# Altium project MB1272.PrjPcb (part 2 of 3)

## Sheet Peripherals.SchDoc: Peripherals
size A4; Date: 01-DEC-2013; CompanyName: STMicroelectronics; Organization: Microcontrollers Division; Address1: 12, Rue Jules HOROWITZ; Address2: 38019 Grenoble; Address3: FRANCE; DocumentNumber: MB1272; Revision: A-01; SheetNumber: 13; SheetTotal: 15; Project: STM32MP15-DISCO PI

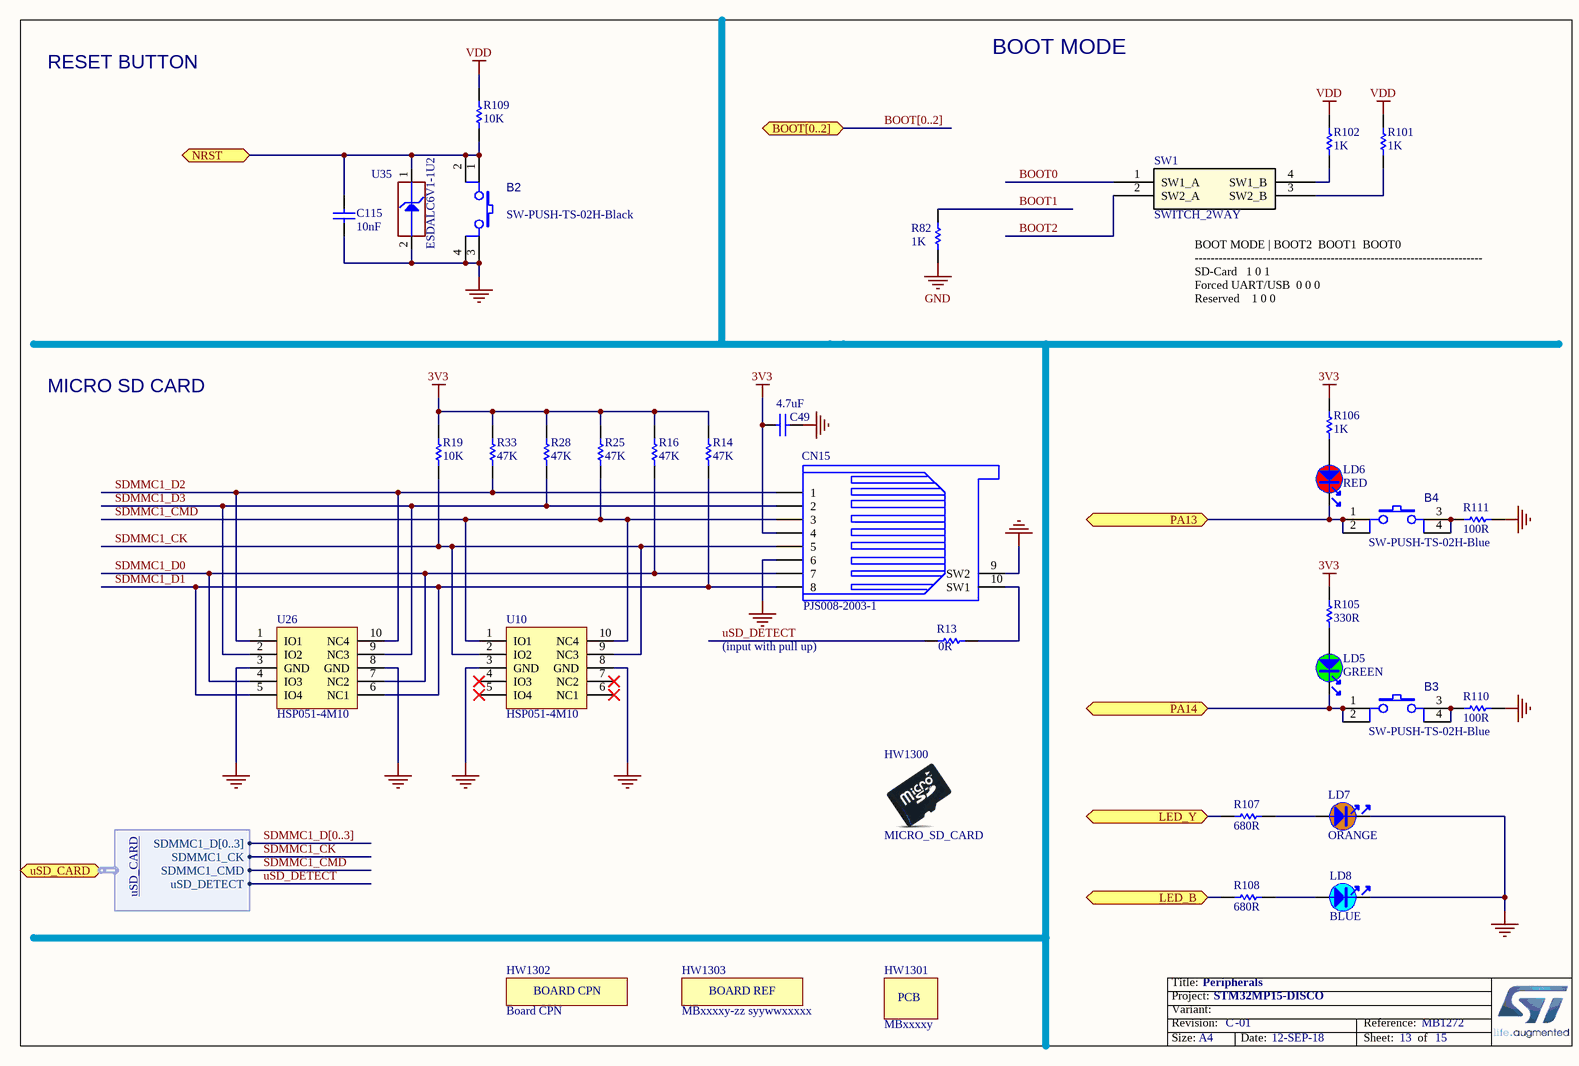
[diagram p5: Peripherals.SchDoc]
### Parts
B2  value SW-PUSH-TS-02H-Black  [SWI_JIUBABA_C-TS-02H-2-5-K-V-T_R_BLACK]
B3  SW-PUSH-TS-02H-Blue  [SWI_JIUBABA_C-TS-02H-2-5-B-V-T_R_BLUE]
B4  SW-PUSH-TS-02H-Blue  [SWI_JIUBABA_C-TS-02H-2-5-B-V-T_R_BLUE]
C49  value 4.7uF  [C0402]  (hidden comment: Capacitor)
C115  value 10nF  [C0402]  (hidden comment: Capacitor)
CN15  value PJS008-2003-1  [CON_MICROSD_YAMAICHI_PJS008-2003-0]
HW1300  Micro_SD_card  (mechanical)
HW1301  value MBxxxxy  (hidden comment: PCB)  (mechanical)
HW1302  value Board CPN  [STICKER_BOARD-CPN_25X5]  (hidden comment: ​PCH W35 footprint requested to have a space on board for stickers.)  (mechanical)
HW1303  value MBxxxxy-zz syywwxxxxx  [STICKER_BOARD-REF_25X5]  (hidden comment: STICKER_BOARD_REF)  (mechanical)
LD5  value GREEN  [LED_0603_GREEN]
LD6  value RED  [LED_0603_RED]
LD7  value ORANGE  [LED_0603_ORANGE_H0P4]  (hidden comment: LED_orange)
LD8  value BLUE  [LED_0603_SMD-B_BLUE_H0P4]  (hidden comment: ​reference from jiubaba)
R13  value 0R  [R0402]
R14  value 47K  [R0402]
R16  value 47K  [R0402]
R19  value 10K  [R0402]
R25  value 47K  [R0402]
R28  value 47K  [R0402]
R33  value 47K  [R0402]
R82  value 1K  [R0402]  (hidden comment: Resistor)
R101  value 1K  [R0402]
R102  value 1K  [R0402]
R105  value 330R  [R0402]
R106  value 1K  [R0402]
R107  value 680R  [R0402]  (hidden comment: Resistor)
R108  value 680R  [R0402]  (hidden comment: Resistor)
R109  value 10K  [R0402]
R110  value 100R  [R0402]
R111  value 100R  [R0402]
SW1  SWITCH_2WAY  [SWI_C&K_SDA02H1SBD_2POS]
U10  HSP051-4M10  [ESD_UQFN-10L_2P5X1_P050]
U26  HSP051-4M10  [ESD_UQFN-10L_2P5X1_P050]
U35  value ESDALC6V1-1U2  [ESD_ST0201]  (hidden comment: ESD-TRANSIL)

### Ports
BOOT[0..2], LED_B, LED_Y, NRST (bidir), PA13, PA14, uSD_CARD (harness uSD_CARD)

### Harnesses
uSD_CARD: SDMMC1_D[0..3], SDMMC1_CK, SDMMC1_CMD, uSD_DETECT

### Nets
3V3: C49.2 CN15.4 R14.2 R16.2 R19.2 R25.2 R28.2 R33.2 R105.2 R106.2
GND: B2.3 B2.4 C49.1 C115.1 CN15.6 CN15.9(SW2) LD7.2 LD8.2 R82.1 R110.2 R111.2 U10.3(GND) U10.8(GND) U26.3(GND) U26.8(GND) U35.2(GND)
VDD: R101.2 R102.2 R109.2
BOOT0: SW1.1(SW1_A)
BOOT1: R82.2
BOOT2: SW1.2(SW2_A)
LED_B: R108.1 ; port LED_B
LED_Y: R107.1 ; port LED_Y
NRST: B2.1 B2.2 C115.2 R109.1 U35.1(IO1) ; port NRST
PA13: B4.1 B4.2 LD6.2 ; port PA13
PA14: B3.1 B3.2 LD5.2 ; port PA14
SDMMC1_CK: CN15.5 R19.1 U10.2(IO2) U10.9(NC3) ; port uSD_CARD.SDMMC1_CK
SDMMC1_CMD: CN15.3 R25.1 U10.1(IO1) U10.10(NC4) ; port uSD_CARD.SDMMC1_CMD
SDMMC1_D0: CN15.7 R16.1 U26.4(IO3) U26.7(NC2)
SDMMC1_D1: CN15.8 R14.1 U26.5(IO4) U26.6(NC1)
SDMMC1_D2: CN15.1 R33.1 U26.1(IO1) U26.10(NC4)
SDMMC1_D3: CN15.2 R28.1 U26.2(IO2) U26.9(NC3)
uSD_DETECT: R13.1 ; port uSD_CARD.uSD_DETECT
NetB3_3: B3.3 B3.4 R110.1
NetB4_3: B4.3 B4.4 R111.1
NetCN15_10: CN15.10(SW1) R13.2
NetLD5_1: LD5.1 R105.1
NetLD6_1: LD6.1 R106.1
NetLD7_1: LD7.1 R107.2
NetLD8_1: LD8.1 R108.2
NetR101_1: R101.1 SW1.3(SW2_B)
NetR102_1: R102.1 SW1.4(SW1_B)

Not connected (* = marked no-connect by the designer): U10 4(IO3)* 5(IO4)* 6(NC1)* 7(NC2)*

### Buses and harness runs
bus BOOT[0..2] = port BOOT[0..2]
bus SDMMC1_D[0..3]

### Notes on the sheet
- BOOT MODE
- RESET BUTTON
- (near SW1) BOOT MODE	|	BOOT2 	BOOT1 	BOOT0
  ------------------------------------------------------------------------
  SD-Card			1	0	1
  Forced UART/USB		0	0	0
  Reserved 			1	0	0
- MICRO SD CARD
- (input with pull up)

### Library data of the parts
B2 = MCD-00171: Switch HW SMD black; Manufacturer_Part_Number: C-TS-02H-2.5-K-V-T/R BLACK; Manufacturer: JIUBABA; Part_Type: Misc; Provided_By: SUBCO; Initial_Board_Reference: MB1264
B3 B4 = MCD-00172: Switch HW SMD blue; Part_Type: Misc; Manufacturer_Part_Number: C-TS-02H-2.5-B-V-T/R BLUE; Manufacturer: JIUBABA; Provided_By: SUBCO; Initial_Board_Reference: MB1264
C49 = MCD-01356: Capacitor, MLCC, 4.7uF, 6V3, X5R, 20%, 0402, T=0,5mm; Manufacturer_Part_Number: GRM155R60J475ME47; Manufacturer: MURATA; Provided_By: SUBCO
C115 = MCD-00011: Capacitor, MLCC, 10nF, 16V, X7R, 10%, 0402, T=0.5mm; Manufacturer_Part_Number: CC0402KRX7R7BB103; Manufacturer: YAGEO; Provided_By: SUBCO; Initial_Board_Reference: MB1274
CN15 = MCD-00023: MicroSD Card Conn, Reversed-Type, Mnt Push-Push; Manufacturer: YAMAICHI; Part_Type: Connector; Provided_By: SUBCO; Initial_Board_Reference: mb1274
HW1300 = MCD-01200: MICRO_SD_CARD Standard min 4GB; Part_Type: Misc; Manufacturer: NETAC; Alternate_Manufacturer: Jiubaba; Alternate_Manufacturer_Part_Number: 988.05.20.3.00018; Provided_By: SUBCO; Initial_Board_Reference: MB1372
HW1301 = MCD-00216: PCB, xxxx for PCB ref, Y for revision; Part_Type: Mechanical; Provided_By: SUBCO; Initial_Board_Reference: MB1319
HW1302 = MCD-00547: Sticker to mention board CPN code; Part_Type: Mechanical; Provided_By: SUBCO; Initial_Board_Reference: MB1319
HW1303 = MCD-00235: Sticker to mention board reference + serial number; Part_Type: Mechanical; Provided_By: SUBCO; Initial_Board_Reference: MB1319
LD5 = MCD-00050: LED, Green, 0603; Manufacturer_Part_Number: 19-213SYGC/S530-E2/TR8; Manufacturer: EVERLIGHT; Part_Type: Display; ECCN_US: EAR99; ECCN_EU: NEC; Provided_By: SUBCO; Initial_Board_Reference: mb1274
LD6 = MCD-00049: LED, Red, 0603; Manufacturer_Part_Number: 19-213-R6C-AP1Q2B/3T; Manufacturer: EVERLIGHT; Part_Type: Display; ECCN_US: EAR99; ECCN_EU: NEC; Provided_By: SUBCO; Initial_Board_Reference: mb1274
LD7 = MCD-00321: LED, Orange, 0603; Part_Type: Display; Manufacturer_Part_Number: 19-217/S2C-AM2N2VY/3T; Manufacturer: EVERLIGHT; ECCN_US: EAR99; ECCN_EU: NEC; Provided_By: SUBCO; Initial_Board_Reference: MB1311
LD8 = MCD-01131: LED Blue, 0603 SMD, Forward Voltage Min=2,8V, Max=3,1V; Part_Type: Display; Manufacturer_Part_Number: 19-217-BHC-ZL1M2RY-3T; Manufacturer: EVERLIGHT; Provided_By: SUBCO; Initial_Board_Reference: MB1272
R13 = MCD-00052: Resistor,0R,0402,5%,1/16W; Manufacturer_Part_Number: RC0402JR-070RL; Manufacturer: YAGEO; Provided_By: SUBCO; Initial_Board_Reference: mb1274
R14 R16 R25 R28 R33 = MCD-00063: Resistor,47K,0402,1%,1/16W; Manufacturer_Part_Number: RC0402FR-0747KL; Manufacturer: YAGEO; Provided_By: SUBCO; Initial_Board_Reference: mb1274
R19 R109 = MCD-00053: Resistor,10K,0402,1%,1/16W; Manufacturer_Part_Number: RC0402FR-0710KL; Manufacturer: YAGEO; Provided_By: SUBCO; Initial_Board_Reference: mb1274
R82 = MCD-00061: Resistor,1K,0402,1%,1/16W; Manufacturer_Part_Number: RC0402FR-071KL; Manufacturer: YAGEO; Provided_By: SUBCO; Initial_Board_Reference: MB1274
R101 R102 R106 = MCD-00061: Resistor,1K,0402,1%,1/16W; Manufacturer_Part_Number: RC0402FR-071KL; Manufacturer: YAGEO; Provided_By: SUBCO; Initial_Board_Reference: mb1274
R105 = MCD-00062: Resistor,330R,0402,1%,1/16W; Manufacturer_Part_Number: RC0402FR-07330RL; Manufacturer: YAGEO; Provided_By: SUBCO; Initial_Board_Reference: mb1274
R107 R108 = MCD-00507: Resistor,680R,0402,1%,1/16W; Manufacturer_Part_Number: RC0402FR-07680RL; Manufacturer: YAGEO; Provided_By: SUBCO
R110 R111 = MCD-00067: Resistor,100R,0402,1%,1/16W; Manufacturer_Part_Number: RC0402FR-07100RL; Manufacturer: YAGEO; Provided_By: SUBCO; Initial_Board_Reference: mb1274
SW1 = MCD-00658: Dip Switch ,2Position ,Surface Mount Slide (Standard) ,2.54 pitch,25mA 24VDC; Part_Type: Misc; Manufacturer_Part_Number: SDA02H1SBD; Manufacturer: C&K; Provided_By: SUBCO; Initial_Board_Reference: MB1272
U10 U26 = MCD-00667: 4-line ESD protection for high speed lines; Part_Type: Diode; Manufacturer: STMICROELECTRONICS; BMS_Part_Number: 9179041; ECCN_US: EAR99; ECCN_EU: NEC; Provided_By: SUBCO with ST control; Initial_Board_Reference: MB1331
U35 = MCD-00170: ESD protection 6V1; Part_Type: Diode; Manufacturer: STMICROELECTRONICS; BMS_Part_Number: 9151132; ECCN_US: EAR99; ECCN_EU: NEC; Provided_By: SUBCO with ST control; Initial_Board_Reference: MB1274

## Sheet ST_LINK_V2-1.SCHDOC: ST-LINK/V2-1 with support of SWD only
size A4; Author: A.B; CompanyName: STMicroelectronics; Organization: Microcontrollers Division; Address1: 12, Rue Jules HOROWITZ; Address2: 38019 Grenoble; Address3: FRANCE; DocumentNumber: MB1272; Revision: A-01; SheetNumber: 15; SheetTotal: 15; Project: STM32MP15-DISCO PI

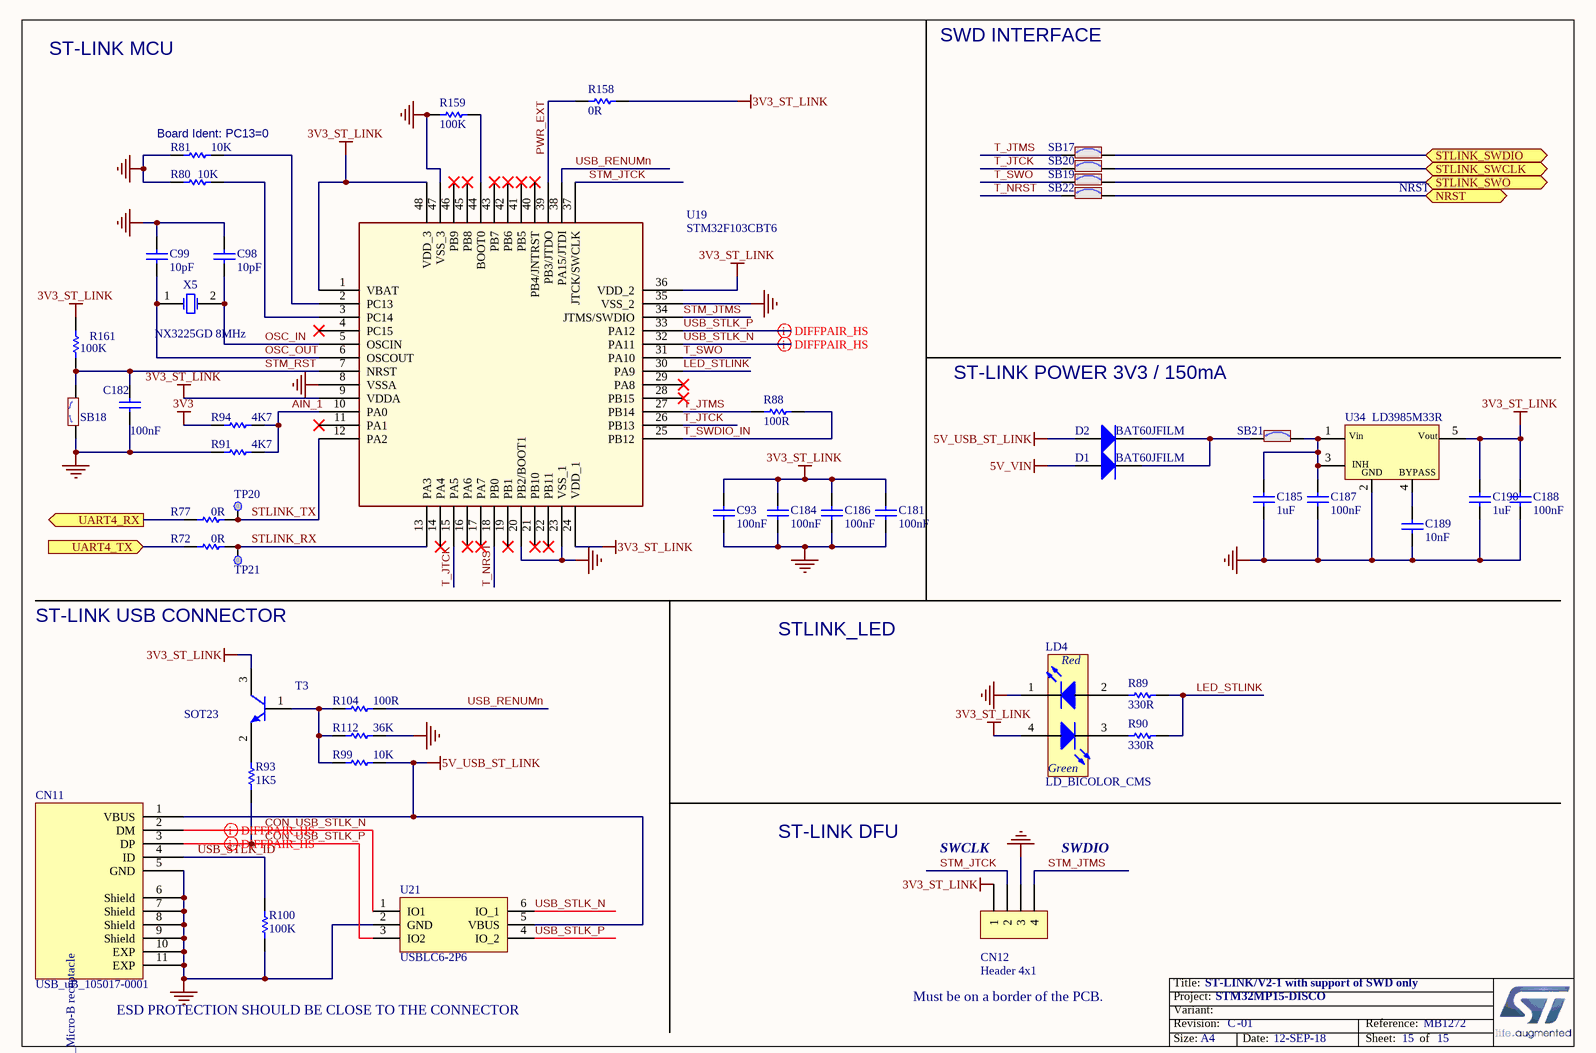
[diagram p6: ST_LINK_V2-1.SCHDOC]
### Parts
C93  value 100nF  [C0402]
C98  value 10pF  [C0402]
C99  value 10pF  [C0402]
C181  value 100nF  [C0402]
C182  value 100nF  [C0402]
C184  value 100nF  [C0402]
C185  value 1uF  [C0603]
C186  value 100nF  [C0402]
C187  value 100nF  [C0402]
C188  value 100nF  [C0402]
C189  value 10nF  [C0402]
C190  value 1uF  [C0603]
CN11  value USB_uB_105017-0001  [CON_USBMICROB_MOLEX_105017-0001_H2P90]
CN12  value Header 4x1  [CON_SAMTEC_TSW-104-07-G-S]
D1  value BAT60JFILM  [DIO_SOD323]
D2  value BAT60JFILM  [DIO_SOD323]
LD4  value LD_BICOLOR_CMS  [LED_BI-GR_HSMF-A201-A00J1]
R72  value 0R  [R0402]
R77  value 0R  [R0402]
R80  value 10K  [R0402]
R81  value 10K  [R0402]
R88  value 100R  [R0402]
R89  value 330R  [R0402]
R90  value 330R  [R0402]
R91  value 4K7  [R0402]
R93  value 1K5  [R0402]
R94  value 4K7  [R0402]
R99  value 10K  [R0402]
R100  value 100K  [R0402]
R104  value 100R  [R0402]
R112  value 36K  [R0402]
R158  value 0R  [R0402]
R159  value 100K  [R0402]
R161  value 100K  [R0402]
SB17  (no value)  [SOLDER-BRIDGE_R0603-0R]
SB18  (no value)  [SOLDER-BRIDGE_R0603-0R]
SB19  (no value)  [SOLDER-BRIDGE_R0603-0R]
SB20  (no value)  [SOLDER-BRIDGE_R0603-0R]
SB21  (no value)  [SOLDER-BRIDGE_R0603-0R]
SB22  (no value)  [SOLDER-BRIDGE_R0603-0R]
T3  value SOT23  [NPN_SOT23]
TP20  Test Point  [TP_SMD_1MM]  (value not drawn)  (no BOM)
TP21  Test Point  [TP_SMD_1MM]  (value not drawn)  (no BOM)
U19  value STM32F103CBT6  [ICC_LQFP48_7X7_P050]
U21  value USBLC6-2P6  [ESD_SOT666]
U34  value LD3985M33R  [REG_SOT23-5L]
X5  value NX3225GD 8MHz  [CRY_NX3225GD_2P]

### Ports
NRST (bidir), STLINK_SWCLK, STLINK_SWDIO, STLINK_SWO, UART4_RX (out), UART4_TX (in)

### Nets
3V3: R94.1
3V3_ST_LINK: C93.2 C181.2 C184.2 C186.2 C188.2 C190.2 CN12.1 LD4.4(YellowGreen_anode) R158.2 R161.2 T3.3(C) U19.1(VBAT) U19.9(VDDA) U19.24(VDD_1) U19.36(VDD_2) U19.48(VDD_3) U34.5(Vout)
5V_USB_ST_LINK: CN11.1(VBUS) D2.1(A) R99.1 U21.5(VBUS)
5V_VIN: D1.1(A)
GND: C93.1 C98.2 C99.2 C181.1 C182.1 C184.1 C185.2 C186.1 C187.1 C188.1 C189.1 C190.1 CN11.5(GND) CN11.6(Shield) CN11.7(Shield) CN11.8(Shield) CN11.9(Shield) CN11.10(EXP) CN11.11(EXP) CN12.3 LD4.1(RED_cathode) R80.1 R81.2 R91.1 R100.1 R112.1 R159.1 SB18.1 U19.8(VSSA) U19.20(PB2/BOOT1) U19.23(VSS_1) U19.35(VSS_2) U19.47(VSS_3) U21.2(GND) U34.2(GND)
AIN_1: R91.2 R94.2 U19.10(PA0)
CON_USB_STLK_N: CN11.2(DM) U21.1(IO1)
CON_USB_STLK_P: CN11.3(DP) R93.1 U21.3(IO2)
JTDO_TRACESWO: SB19.2 ; port STLINK_SWO
LED_STLINK: R89.2 R90.2 U19.30(PA9)
NRST: SB22.2 ; port NRST
OSC_IN: C98.1 U19.5(OSCIN) X5.2(OSC2)
OSC_OUT: C99.1 U19.6(OSCOUT) X5.1(OSC1)
PWR_EXT: R158.1 U19.39(PB3/JTDO)
STLINK_RX: R72.2 TP21.1 U19.13(PA3)
STLINK_SWCLK: SB20.2 ; port STLINK_SWCLK
STLINK_SWDIO: SB17.2 ; port STLINK_SWDIO
STLINK_TX: R77.1 TP20.1 U19.12(PA2)
STM_JTCK: CN12.2 U19.37(JTCK/SWCLK)
STM_JTMS: CN12.4 U19.34(JTMS/SWDIO)
STM_RST: C182.2 R161.1 SB18.2 U19.7(NRST)
T_JTCK: SB20.1 U19.15(PA5) U19.26(PB13)
T_JTMS: R88.1 SB17.1 U19.27(PB14)
T_NRST: SB22.1 U19.18(PB0)
T_SWDIO_IN: R88.2 U19.25(PB12)
T_SWO: SB19.1 U19.31(PA10)
UART4_RX: R77.2 ; port UART4_RX
UART4_TX: R72.1 ; port UART4_TX
USB_RENUMn: R104.2 U19.38(PA15/JTDI)
USB_STLK_ID: CN11.4(ID) R100.2
USB_STLK_N: U19.32(PA11) U21.6(IO_1)
USB_STLK_P: U19.33(PA12) U21.4(IO_2)
NetC185_1: C185.1 C187.2 SB21.2 U34.1(Vin) U34.3(CE)
NetC189_2: C189.2 U34.4(BYPASS)
NetD1_2: D1.2(K) D2.2(K) SB21.1
NetLD4_2: LD4.2(Red_anode) R89.1
NetLD4_3: LD4.3(YellowGreen_cathode) R90.1
NetR80_2: R80.2 U19.3(PC14)
NetR81_1: R81.1 U19.2(PC13)
NetR93_2: R93.2 T3.2(E)
NetR99_2: R99.2 R104.1 R112.2 T3.1(B)
NetR159_2: R159.2 U19.44(BOOT0)

Not connected (* = marked no-connect by the designer): U19 4(PC15)* 11(PA1)* 14(PA4)* 16(PA6)* 17(PA7)* 19(PB1)* 21(PB10)* 22(PB11)* 28(PB15)* 29(PA8)* 40(PB4/JNTRST)* 41(PB5)* 42(PB6)* 43(PB7)* 45(PB8)* 46(PB9)*

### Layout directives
differential pair: CON_USB_STLK_N, CON_USB_STLK_P, USB_STLK_N, USB_STLK_P

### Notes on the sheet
- ST-LINK MCU
- SWD INTERFACE
- (near R81) Board Ident: PC13=0
- NRST
- ST-LINK POWER 3V3 / 150mA
- ST-LINK USB CONNECTOR
- STLINK_LED
- ST-LINK DFU
- SWCLK
- SWDIO
- Must be on a border of the PCB.
- (near CN11) ESD PROTECTION SHOULD BE CLOSE TO THE CONNECTOR

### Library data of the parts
C93 C181 C182 C184 C186-C188 = MCD-00006: Capacitor,100nF,16V,X7R,10%,0402; Manufacturer_Part_Number: CC0402KRX7R7BB104; Manufacturer: YAGEO; Alternate_Manufacturer: MURATA; Alternate_Manufacturer_Part_Number: GCM155R71C104KA55D; Provided_By: SUBCO; Initial_Board_Reference: mb1274
C98 C99 = MCD-00015: Capacitor,10pF,50V,NPO,5%,0402; Manufacturer_Part_Number: CC0402JRNPO9BN100; Manufacturer: YAGEO; Provided_By: SUBCO; Initial_Board_Reference: mb1274
C185 C190 = MCD-00238: Capacitor,1uF,6V3,X5R,10%,0603; Manufacturer_Part_Number: CC0603KRX5R5BB105; Manufacturer: YAGEO; Provided_By: SUBCO; Initial_Board_Reference: mb1319
C189 = MCD-00011: Capacitor,10nF,16V,X7R,10%,0402; Manufacturer_Part_Number: CC0402KRX7R7BB103; Manufacturer: YAGEO; Provided_By: SUBCO; Initial_Board_Reference: mb1274
CN11 = MCD-00028: USB-MICRO-B, 0.65mm, RA, SMT, Bottom Mount,; Manufacturer_Part_Number: 1050170001; Manufacturer: MOLEX; Part_Type: Connector; Provided_By: SUBCO; Initial_Board_Reference: mb1274
CN12 = MCD-00029: Header, 4x1, 2,54mm, VR, TH, Height 5.84mm/2.54mm; Manufacturer_Part_Number: TSW-104-07-x-S; Manufacturer: SAMTEC; Part_Type: Connector; Provided_By: SUBCO; Initial_Board_Reference: mb1274
D1 D2 = MCD-00034: BAT60JFILM; Manufacturer: STMICROELECTRONICS; Part_Type: Diode; BMS_Part_Number: 9151097; ECCN_US: EAR99; ECCN_EU: NEC; Provided_By: SUBCO with ST control; Initial_Board_Reference: mb1274
LD4 = MCD-00051: LED Bicolor; Manufacturer_Part_Number: HSMF-A201-A00J1; Manufacturer: AVAGO TECHNOLOGIES; Alternate_Manufacturer_Part_Number: LE-RGW35280; Alternate_Manufacturer: EVERLUCK; Part_Type: Display; ECCN_US: EAR99; ECCN_EU: NEC; Provided_By: SUBCO; Initial_Board_Reference: mb1274
R72 R77 R158 = MCD-00052: as R13 on sheet Peripherals
R80 R81 R99 = MCD-00053: as R19 on sheet Peripherals
R88 R104 = MCD-00067: as R110 on sheet Peripherals
R89 R90 = MCD-00062: as R105 on sheet Peripherals
R91 R94 = MCD-00065: Resistor,4K7,0402,1%,1/16W; Manufacturer_Part_Number: RC0402FR-074K7L; Manufacturer: YAGEO; Alternate_Manufacturer_Part_Number: RT0402FRE074K7L; Provided_By: SUBCO; Initial_Board_Reference: mb1274
R93 = MCD-00068: Resistor,1K5,0402,1%,1/16W; Manufacturer_Part_Number: RC0402FR-071K5L; Manufacturer: YAGEO; Provided_By: SUBCO; Initial_Board_Reference: mb1274
R100 R159 R161 = MCD-00059: Resistor,100K,0402,1%,1/16W; Manufacturer_Part_Number: RC0402FR-07100KL; Manufacturer: YAGEO; Alternate_Manufacturer_Part_Number: RT0402FRE07100KL; Provided_By: SUBCO; Initial_Board_Reference: mb1274
R112 = MCD-00069: Resistor,36K,0402,1%,1/16W; Manufacturer_Part_Number: RC0402FR-0736KL; Manufacturer: YAGEO; Provided_By: SUBCO; Initial_Board_Reference: mb1274
SB17 SB19-SB22 = MCD-00071: Solder Bridge ON; Part_Type: Mechanical; Manufacturer: YAGEO; Manufacturer_Part_Number: RC0603JR-070RL; Provided_By: SUBCO; Initial_Board_Reference: mb1274
SB18 = MCD-00072: Solder Bridge OFF; Part_Type: Mechanical; Manufacturer: YAGEO; Manufacturer_Part_Number: RC0603JR-070RL; Provided_By: SUBCO; Initial_Board_Reference: mb1274
T3 = MCD-00073: NPN Bipolar Transistor; Manufacturer_Part_Number: BSR14; Manufacturer: ON SEMICONDUCTOR; Part_Type: IC; Alternate_Manufacturer_Part_Number: MMBT2222ALT1G / MMBT2222ALT3G; ECCN_US: EAR99; ECCN_EU: NEC; Provided_By: SUBCO; Initial_Board_Reference: mb1274
TP20 TP21 = MCD-00074: Test Point 1mm; Part_Type: Mechanical; Initial_Board_Reference: MB1274
U19 = MCD-00085: Medium-density performance line ARM-based 32-bit MCU with 128KB Flash; Manufacturer: STMICROELECTRONICS; Part_Type: IC; BMS_Part_Number: 9175111; ECCN_US: 3A991A2; ECCN_EU: NEC; Provided_By: SUBCO with ST control; Initial_Board_Reference: mb1274
U21 = MCD-00169: USB OTG FS ESD protection; Manufacturer: STMICROELECTRONICS; Part_Type: IC; BMS_Part_Number: 9151057; Provided_By: SUBCO with ST control; ECCN_US: EAR99; ECCN_EU: NEC; Initial_Board_Reference: MB1274
U34 = MCD-00086: Ultra low drop-low noise BiCMOS voltage, regulators low ESR capacitors compatible; Manufacturer: STMICROELECTRONICS; Part_Type: IC; BMS_Part_Number: 9176161; ECCN_US: EAR99; ECCN_EU: NEC; Provided_By: SUBCO with ST control; Initial_Board_Reference: mb1274
X5 = MCD-00092: Crystal 8Mhz, 8pF, -+50PPM, SMD; Manufacturer_Part_Number: NX3225GD 8MHz EXS00A-CG04874; Manufacturer: NDK; Part_Type: Crystal_Osc; BMS_Part_Number: 9157029; ECCN_US: EAR99; ECCN_EU: NEC; Provided_By: SUBCO; Initial_Board_Reference: mb1274

## Sheet GPIO_&_Arduino_ Connectors.SchDoc: GPIO_&_Arduino_ Connectors
size A3; CompanyName: STMicroelectronics; Organization: Microcontrollers Division; Address1: 12, Rue Jules HOROWITZ; Address2: 38019 Grenoble; Address3: FRANCE; DocumentNumber: MB1272; Revision: A-01; SheetNumber: 10; SheetTotal: 15; Project: STM32MP15-DISCO PI

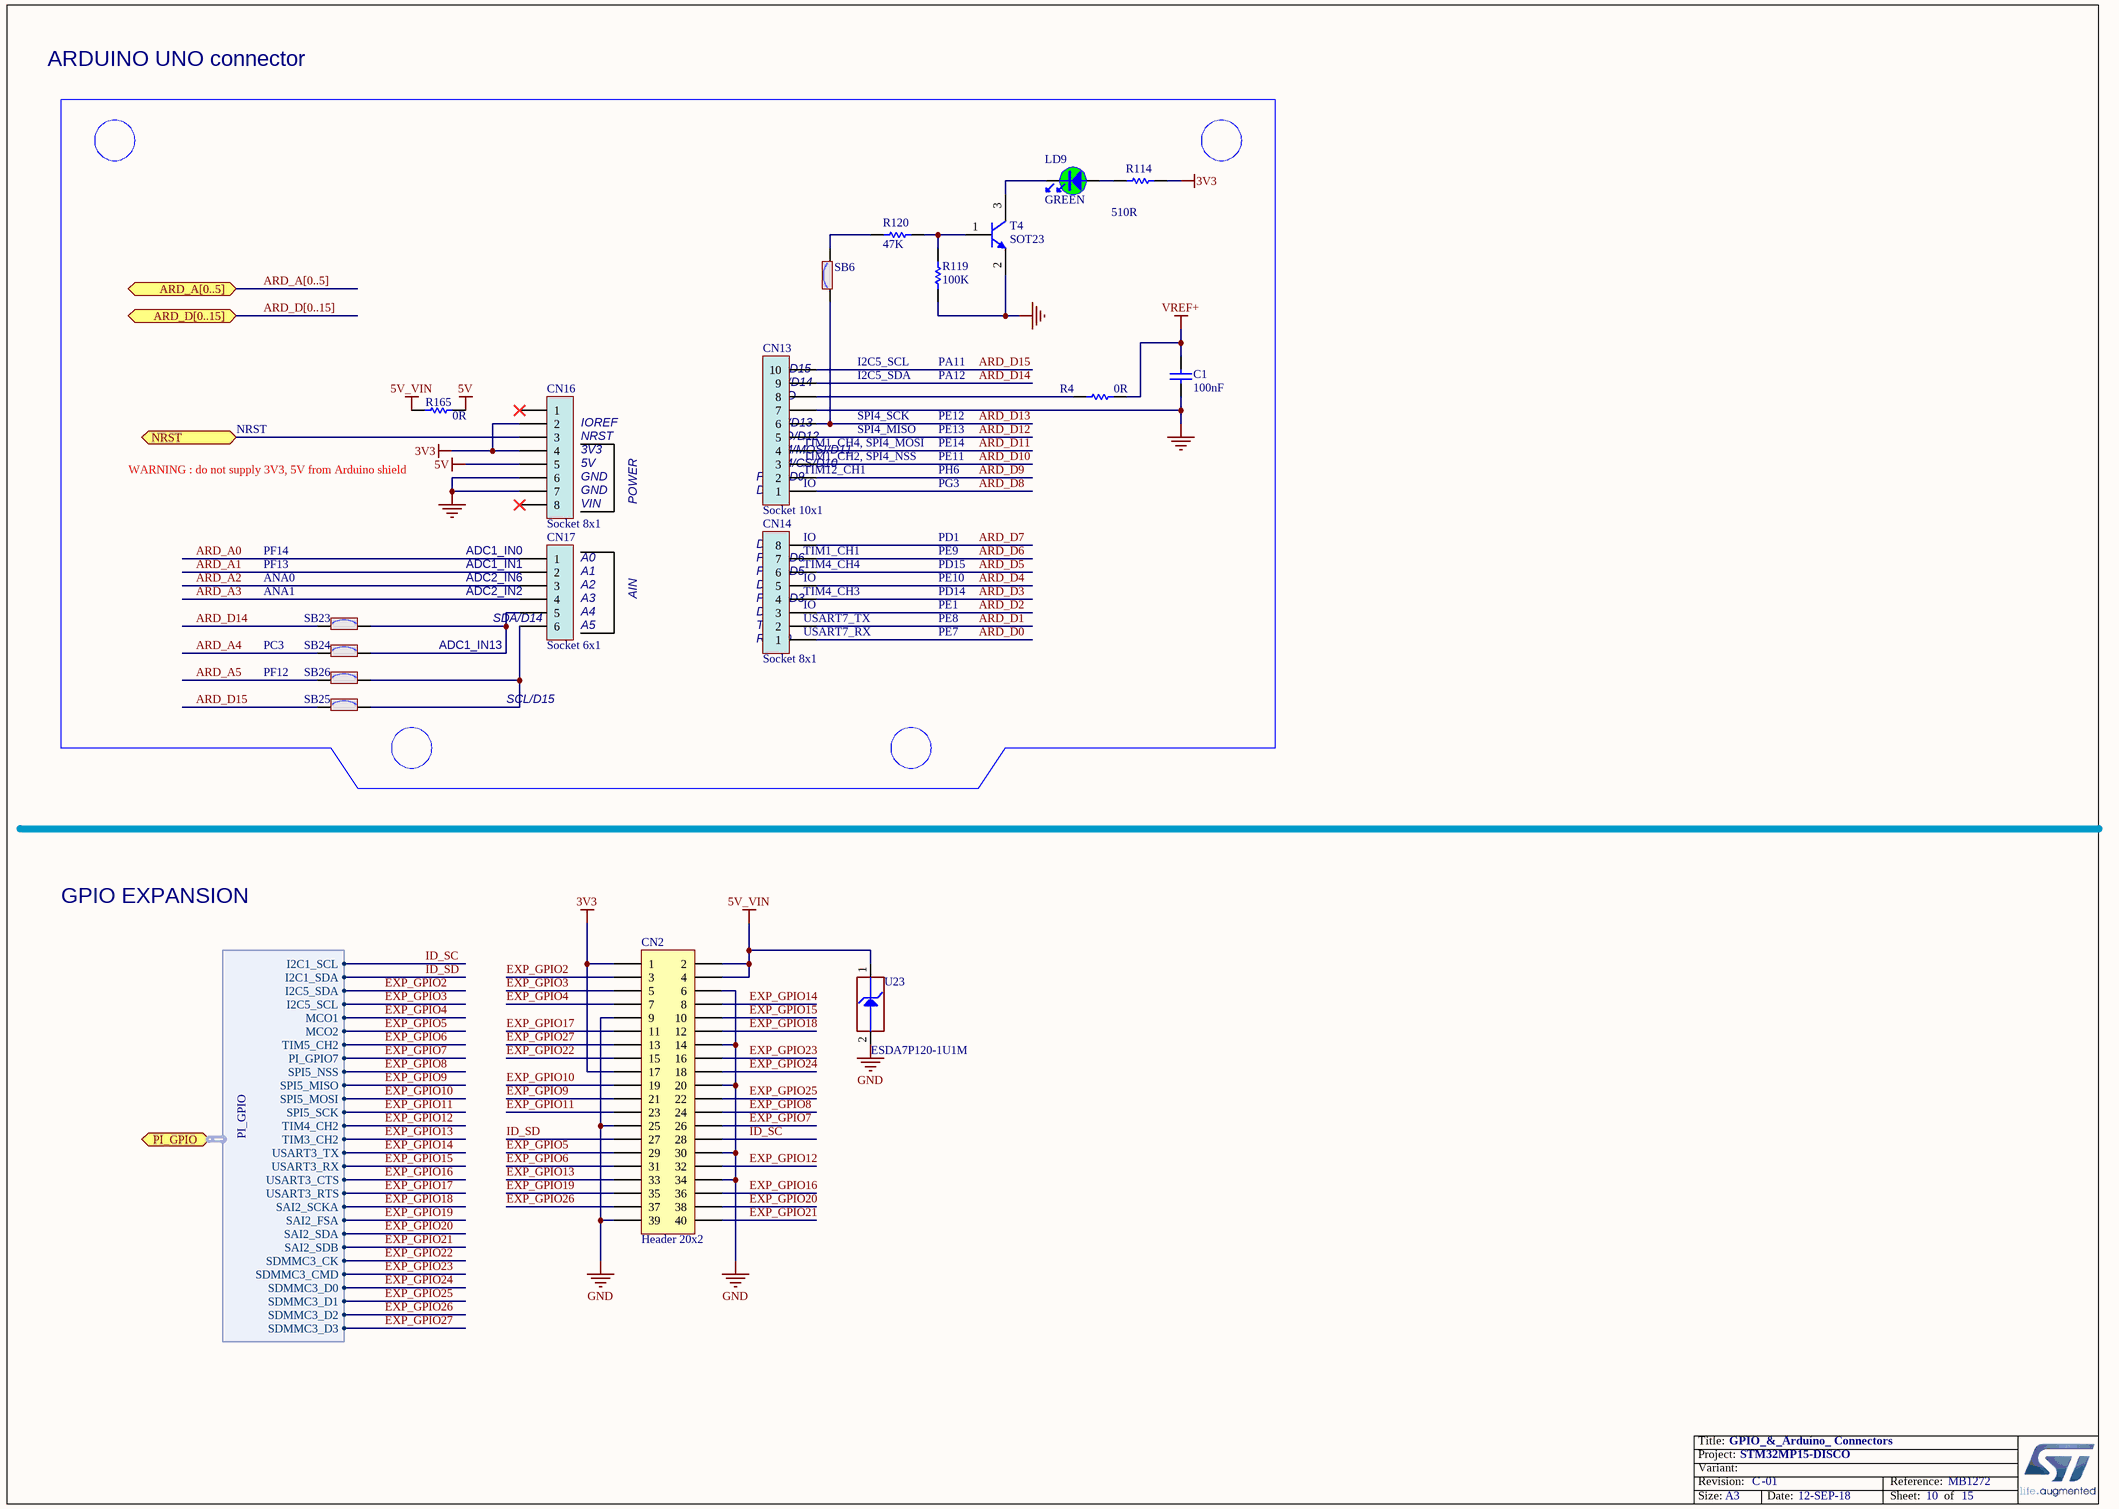
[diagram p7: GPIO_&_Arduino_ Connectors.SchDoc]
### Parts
C1  value 100nF  [C0402]
CN2  value Header 20x2  [CON_SAMTEC_TSW-120-07-G-D]
CN13  value Socket 10x1  [CON_SAMTEC_SSW-110-22-X-S-VS]
CN14  value Socket 8x1  [CON_SAMTEC_SSW-108-22-X-S-VS]
CN16  value Socket 8x1  [CON_SAMTEC_SSW-108-22-X-S-VS]
CN17  value Socket 6x1  [CON_SAMTEC_SSW-106-22-X-S-VS]
LD9  value GREEN  [LED_0603_GREEN]
R4  value 0R  [R0402]
R114  value 510R  [R0402]
R119  value 100K  [R0402]
R120  value 47K  [R0402]
R165  value 0R  [R0402]
SB6  (no value)  [SOLDER-BRIDGE_R0603-0R]
SB23  SB_ON  [SOLDER-BRIDGE_R0603-0R]  (value not drawn)
SB24  (no value)  [SOLDER-BRIDGE_R0603-0R]
SB25  SB_ON  [SOLDER-BRIDGE_R0603-0R]  (value not drawn)
SB26  (no value)  [SOLDER-BRIDGE_R0603-0R]
T4  value SOT23  [NPN_SOT23]
U23  value ESDA7P120-1U1M  [ESD_QFN1610_2N_1K_2A]  (hidden comment: ​Footprint needed DFN105P160X60-2N)

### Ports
ARD_A[0..5], ARD_D[0..15], NRST (bidir), PI_GPIO (harness PI_GPIO)

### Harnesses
PI_GPIO: I2C1_SCL, I2C1_SDA, I2C5_SDA, MCO1, MCO2, TIM5_CH2, PI_GPIO7, SPI5_NSS, SPI5_MISO, SPI5_MOSI, SPI5_SCK, TIM4_CH2, TIM3_CH2, USART3_TX, USART3_RX, USART3_CTS, USART3_RTS, SDMMC3_CK, SDMMC3_CMD, SDMMC3_D0, SDMMC3_D1, SDMMC3_D2, SDMMC3_D3, I2C5_SCL, SAI2_SCKA, SAI2_FSA, SAI2_SDA, SAI2_SDB

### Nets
3V3: CN2.1 CN2.17 CN16.2 CN16.4 R114.2
5V: CN16.5 R165.2
5V_VIN: CN2.2 CN2.4 R165.1 U23.1(IO1)
GND: C1.1 CN2.6 CN2.9 CN2.14 CN2.20 CN2.25 CN2.30 CN2.34 CN2.39 CN13.7 CN16.6 CN16.7 R119.1 T4.2(E) U23.2(GND)
VREF+: C1.2 R4.2
ARD_A0: CN17.1
ARD_A1: CN17.2
ARD_A2: CN17.3
ARD_A3: CN17.4
ARD_A4: SB24.1
ARD_A5: SB26.1
ARD_D0: CN14.1
ARD_D1: CN14.2
ARD_D2: CN14.3
ARD_D3: CN14.4
ARD_D4: CN14.5
ARD_D5: CN14.6
ARD_D6: CN14.7
ARD_D7: CN14.8
ARD_D8: CN13.1
ARD_D9: CN13.2
ARD_D10: CN13.3
ARD_D11: CN13.4
ARD_D12: CN13.5
ARD_D13: CN13.6 SB6.1
ARD_D14: CN2.3 CN13.9 SB23.1 ; port PI_GPIO.I2C5_SDA  [also labelled EXP_GPIO2]
ARD_D15: CN2.5 CN13.10 SB25.1 ; port PI_GPIO.I2C5_SCL  [also labelled EXP_GPIO3]
EXP_GPIO4: CN2.7 ; port PI_GPIO.MCO1
EXP_GPIO5: CN2.29 ; port PI_GPIO.MCO2
EXP_GPIO6: CN2.31 ; port PI_GPIO.TIM5_CH2
EXP_GPIO7: CN2.26 ; port PI_GPIO.PI_GPIO7
EXP_GPIO8: CN2.24 ; port PI_GPIO.SPI5_NSS
EXP_GPIO9: CN2.21 ; port PI_GPIO.SPI5_MISO
EXP_GPIO10: CN2.19 ; port PI_GPIO.SPI5_MOSI
EXP_GPIO11: CN2.23 ; port PI_GPIO.SPI5_SCK
EXP_GPIO12: CN2.32 ; port PI_GPIO.TIM4_CH2
EXP_GPIO13: CN2.33 ; port PI_GPIO.TIM3_CH2
EXP_GPIO14: CN2.8 ; port PI_GPIO.USART3_TX
EXP_GPIO15: CN2.10 ; port PI_GPIO.USART3_RX
EXP_GPIO16: CN2.36 ; port PI_GPIO.USART3_CTS
EXP_GPIO17: CN2.11 ; port PI_GPIO.USART3_RTS
EXP_GPIO18: CN2.12 ; port PI_GPIO.SAI2_SCKA
EXP_GPIO19: CN2.35 ; port PI_GPIO.SAI2_FSA
EXP_GPIO20: CN2.38 ; port PI_GPIO.SAI2_SDA
EXP_GPIO21: CN2.40 ; port PI_GPIO.SAI2_SDB
EXP_GPIO22: CN2.15 ; port PI_GPIO.SDMMC3_CK
EXP_GPIO23: CN2.16 ; port PI_GPIO.SDMMC3_CMD
EXP_GPIO24: CN2.18 ; port PI_GPIO.SDMMC3_D0
EXP_GPIO25: CN2.22 ; port PI_GPIO.SDMMC3_D1
EXP_GPIO26: CN2.37 ; port PI_GPIO.SDMMC3_D2
EXP_GPIO27: CN2.13 ; port PI_GPIO.SDMMC3_D3
ID_SC: CN2.28 ; port PI_GPIO.I2C1_SCL  [project net I2C1_SCL]
ID_SD: CN2.27 ; port PI_GPIO.I2C1_SDA  [project net I2C1_SDA]
NRST: CN16.3 ; port NRST
NetCN13_8: CN13.8 R4.1
NetCN17_5: CN17.5 SB23.2 SB24.2
NetCN17_6: CN17.6 SB25.2 SB26.2
NetLD9_1: LD9.1 R114.1
NetLD9_2: LD9.2 T4.3(C)
NetR119_2: R119.2 R120.2 T4.1(B)
NetR120_1: R120.1 SB6.2

Not connected (* = marked no-connect by the designer): CN16 1* 8*

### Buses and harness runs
bus ARD_A[0..5] = port ARD_A[0..5]
bus ARD_D[0..15] = port ARD_D[0..15]

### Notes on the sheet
- ARDUINO UNO connector
- (near CN13) SCL/D15
- I2C5_SCL
- I2C5_SDA
- PA11
- PA12
- NRST
- (near CN16) IOREF
- (near CN16) NRST
- (near CN16) 3V3
- (near CN13) SDA/D14
- (near CN13) SCK/D13
- (near CN13) MISO/D12
- (near CN13) PWM/MOSI/D11
- (near CN13) AVDD
- (near CN13) GND
- (near CN13) TIM1_CH4, SPI4_MOSI
- SPI4_SCK
- SPI4_MISO
- PE14
- PE13
- PE12
- WARNING : do not supply 3V3, 5V from Arduino shield
- (near CN16) 5V
- (near CN16) GND
- (near CN16) VIN
- POWER
- (near CN13) D8
- (near CN13) PWM/D9
- (near CN13) PWM/CS/D10
- (near CN13) TIM12_CH1
- (near CN13) TIM1_CH2, SPI4_NSS
- (near CN13) IO
- PG3
- PH6
- PE11
- ANA0
- PF14
- PF13
- (near CN17) ADC2_IN6
- (near CN17) ADC1_IN1
- ADC1_IN0
- (near CN17) A0
- (near CN17) A1
- (near CN17) A2
- (near CN14) D4
- (near CN14) PWM/D5
- (near CN14) PWM/D6
- (near CN14) D7
- (near CN14) TIM4_CH4
- (near CN14) TIM1_CH1
- (near CN14) IO
- PE10
- PD15
- PE9
- PD1
- ANA1
- PC3
- ADC1_IN13
- (near CN17) ADC2_IN2
- SDA/D14
- (near CN17) A3
- (near CN17) A4
- (near CN17) A5
- AIN
- (near CN14) RX/D0
- (near CN14) TX/D1
- (near CN14) D2
- (near CN14) PWM/D3
- (near CN14) USART7_RX
- (near CN14) USART7_TX
- (near CN14) TIM4_CH3
- PE7
- PE8
- PE1
- PD14
- PF12
- SCL/D15
- GPIO EXPANSION

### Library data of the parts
C1 = MCD-00006: as C93 on sheet ST_LINK_V2-1
CN2 = MCD-00302: Header, 20x2, 2.54mm, VR, TH, Height 5.84mm/2.54mm; Manufacturer_Part_Number: TSW-120-07-G-D; Manufacturer: SAMTEC; Part_Type: Connector; Provided_By: SUBCO; Initial_Board_Reference: mb1272
CN13 = MCD-00301: Socket, 10x1, 2.54mm, VR, SMT, Height 9.78mm; Part_Type: Connector; Manufacturer_Part_Number: SSW-110-22-L-S-VS; Manufacturer: SAMTEC; Provided_By: SUBCO; Initial_Board_Reference: mb1272
CN14 CN16 = MCD-00300: Socket, 8x1, 2.54mm, VR, SMT, Height 9.78mm; Manufacturer_Part_Number: SSW-108-22-L-S-VS; Manufacturer: SAMTEC; Part_Type: Connector; Provided_By: SUBCO; Initial_Board_Reference: mb1272
CN17 = MCD-00299: Socket, 6x1, 2.54mm, VR, SMT, Height 9.78mm; Manufacturer_Part_Number: SSW-106-22-L-S-VS; Manufacturer: SAMTEC; Part_Type: Connector; Provided_By: SUBCO; Initial_Board_Reference: mb1272
LD9 = MCD-00050: as LD5 on sheet Peripherals
R4 R165 = MCD-00052: as R13 on sheet Peripherals
R114 = MCD-00064: Resistor,510R,0402,1%,1/16W; Manufacturer_Part_Number: RC0402FR-07510RL; Manufacturer: YAGEO; Provided_By: SUBCO; Initial_Board_Reference: mb1274
R119 = MCD-00059: as R100 on sheet ST_LINK_V2-1
R120 = MCD-00063: as R14 on sheet Peripherals
SB6 SB24 SB26 = MCD-00071: as SB17 on sheet ST_LINK_V2-1
SB23 SB25 = MCD-00071: Solder Bridge ON; Part_Type: Mechanical; Manufacturer: YAGEO; Manufacturer_Part_Number: RC0603JR-070RL; Provided_By: SUBCO; Initial_Board_Reference: MB1274
T4 = MCD-00073: as T3 on sheet ST_LINK_V2-1
U23 = MCD-01026: High power transient voltage suppressor; Part_Type: Diode; Manufacturer: STMICROELECTRONICS; BMS_Part_Number: 9179046; ECCN_US: EAR99; ECCN_EU: NEC; Provided_By: SUBCO with ST control; Initial_Board_Reference: MB1378

## Sheet DSI_LCD.SchDoc: DSI_LCD_connector
size A4; Date: 29-OCT-2015; Author: A.B; CompanyName: STMicroelectronics; Organization: MCD/TOOLS/GNB; Address1: 12, Rue Jules HOROWITZ; Address2: 38019 Grenoble; Address3: FRANCE; DocumentNumber: MB1272; Revision: A-01; SheetNumber: 8; SheetTotal: 15; Project: STM32MP15-DISCO PI

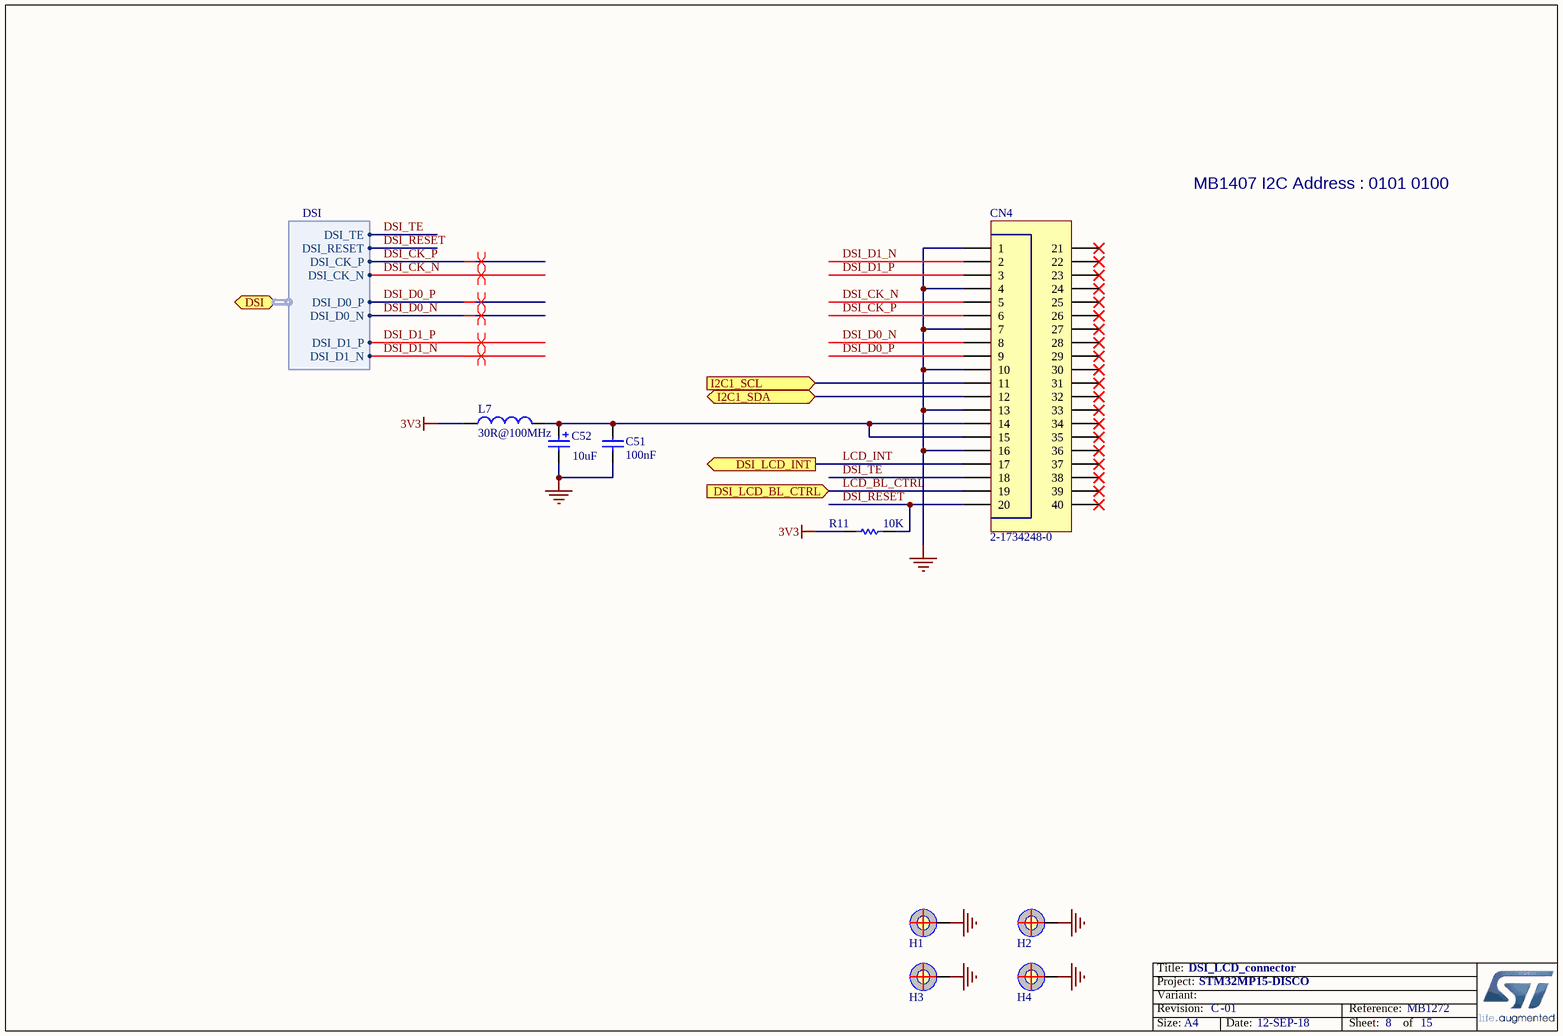
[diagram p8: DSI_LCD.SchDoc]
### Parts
C51  value 100nF  [C0402]
C52  value 10uF  [CPOL_TAJ-A_1206_H180]
CN4  value 2-1734248-0  [CON_TE-CONNECTIVITY_2-1734248-0]
H1  (no value)  [PTH_M1261-3005-N_3P5X6_M3_H14]  (no BOM)
H2  (no value)  [PTH_M1261-3005-N_3P5X6_M3_H14]  (no BOM)
H3  (no value)  [PTH_M1261-3005-N_3P5X6_M3_H14]  (no BOM)
H4  (no value)  [PTH_M1261-3005-N_3P5X6_M3_H14]  (no BOM)
L7  value 30R@100MHz  [L0603]  (hidden comment: BEAD)
R11  value 10K  [R0402]

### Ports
DSI (harness DSI), DSI_LCD_BL_CTRL (in), DSI_LCD_INT (out), I2C1_SCL (in), I2C1_SDA (bidir)

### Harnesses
DSI: DSI_CK_P, DSI_CK_N, DSI_D0_P, DSI_D0_N, DSI_D1_P, DSI_D1_N, DSI_TE, DSI_RESET

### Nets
3V3: L7.1 R11.1
GND: C51.1 C52.2 CN4.1 CN4.4 CN4.7 CN4.10 CN4.13 CN4.16 H1.1 H2.1 H3.1 H4.1
DSI_CK_N: CN4.5 ; port DSI.DSI_CK_N
DSI_CK_P: CN4.6 ; port DSI.DSI_CK_P
DSI_D0_N: CN4.8 ; port DSI.DSI_D0_N
DSI_D0_P: CN4.9 ; port DSI.DSI_D0_P
DSI_D1_N: CN4.2 ; port DSI.DSI_D1_N
DSI_D1_P: CN4.3 ; port DSI.DSI_D1_P
DSI_RESET: CN4.20 R11.2 ; port DSI.DSI_RESET
DSI_TE: CN4.18 ; port DSI.DSI_TE
I2C1_SCL: CN4.11 ; port I2C1_SCL
I2C1_SDA: CN4.12 ; port I2C1_SDA
LCD_BL_CTRL: CN4.19 ; port DSI_LCD_BL_CTRL  [project net DSI_LCD_BL_CTRL]
LCD_INT: CN4.17 ; port DSI_LCD_INT  [project net DSI_LCD_INT]
NetC51_2: C51.2 C52.1 CN4.14 CN4.15 L7.2

Not connected (* = marked no-connect by the designer): CN4 21* 22* 23* 24* 25* 26* 27* 28* 29* 30* 31* 32* 33* 34* 35* 36* 37* 38* 39* 40*

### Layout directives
differential pair: DSI_CK_N, DSI_CK_P, DSI_D0_N, DSI_D0_P, DSI_D1_N, DSI_D1_P

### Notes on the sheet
- MB1407 I2C Address : 0101 0100

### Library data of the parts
C51 = MCD-00006: as C93 on sheet ST_LINK_V2-1
C52 = MCD-00199: Polarized Capacitor,10uF,16V,10%,typeA; Manufacturer_Part_Number: TAJA106K016R; Manufacturer: AVX; Provided_By: SUBCO; ECCN_US: EAR99; ECCN_EU: NEC
CN4 = MCD-01013: Socket ,TEConn,FCC/FPC, 20pins, 1.0mm,SMT, ZIF Receptacle; Part_Type: Connector; Manufacturer: TE CONNECTIVITY; Provided_By: SUBCO; Initial_Board_Reference: MB1272
H1-H4 = MCD-00035: POSITION HOLE C6D3R5; Part_Type: Mechanical; Initial_Board_Reference: mb1274
L7 = MCD-00046: SMD Chip ferrite bead, 30R@100MHz +/-30%, 5A, 10mohm DC, S (Standard) material, 0603, T=0.8mm; Part_Type: Inductor; Manufacturer_Part_Number: MPZ1608S300A; Manufacturer: TDK; Provided_By: SUBCO; Initial_Board_Reference: MB1274
R11 = MCD-00053: as R19 on sheet Peripherals

## Sheet WLAN_BLUETOOTH.SchDoc: WLAN_BLUETOOTH
size A4; Date: 21-MAR-2018; Author: A.B; CompanyName: STMicroelectronics; Organization: MCD/TOOLS/GNB; Address1: 12, Rue Jules HOROWITZ; Address2: 38019 Grenoble; Address3: FRANCE; DocumentNumber: MB1272; Revision: B-01; SheetNumber: 14; SheetTotal: 15; Project: STM32MP15-DISCO PI

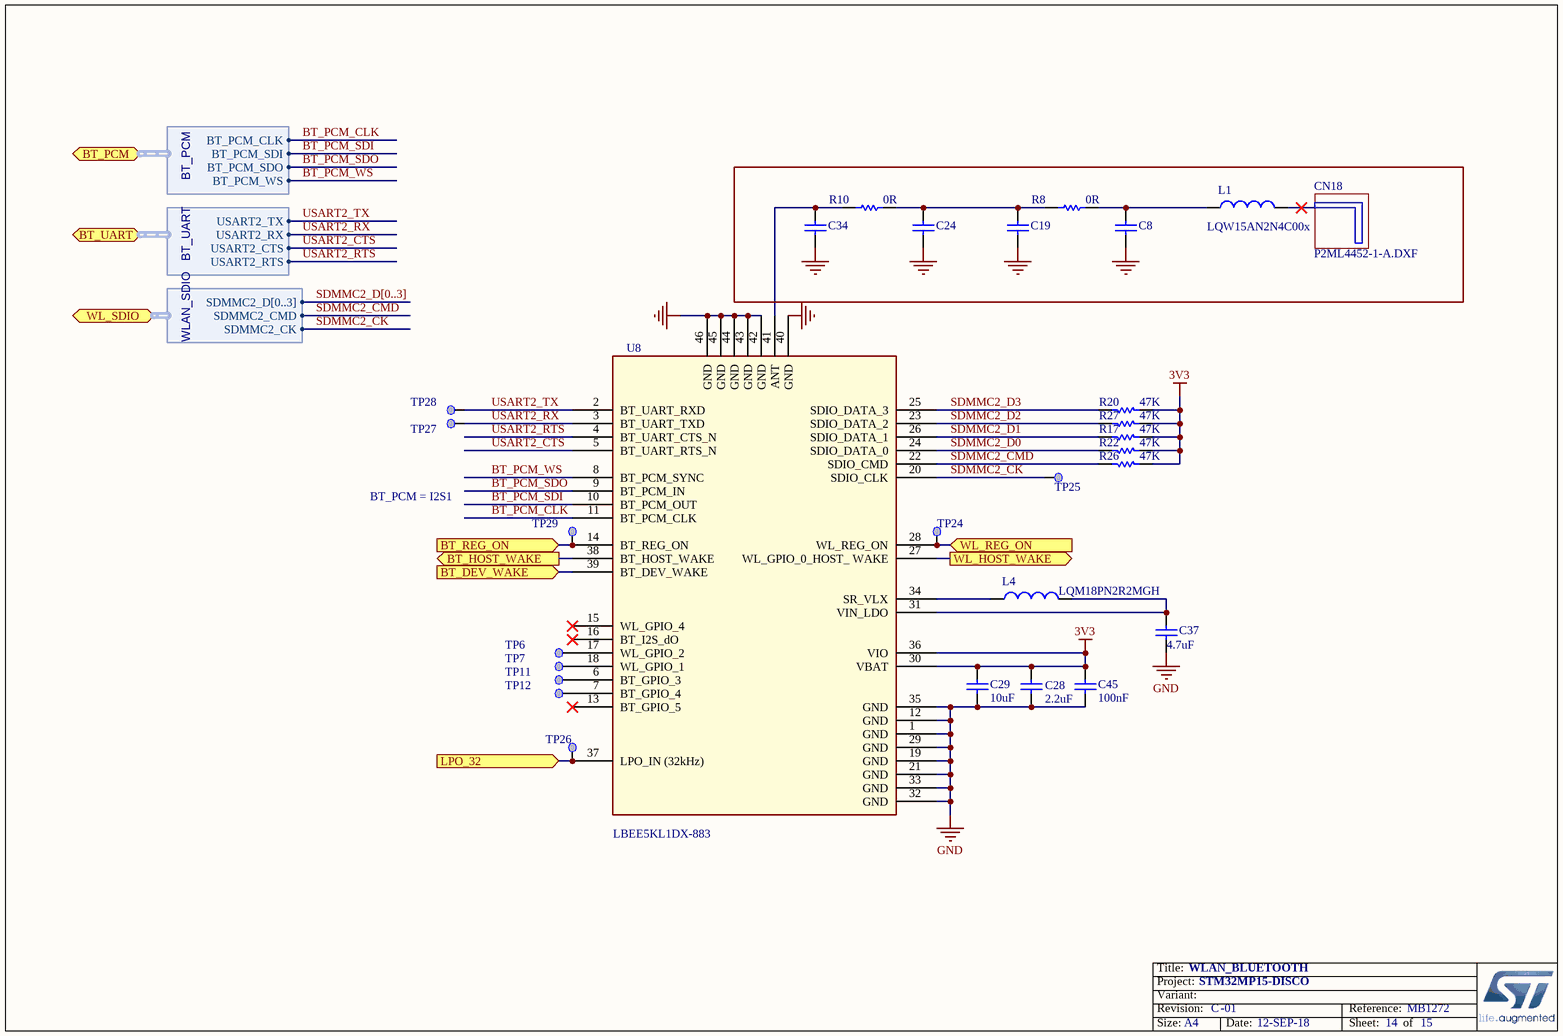
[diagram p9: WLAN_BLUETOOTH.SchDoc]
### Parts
C8  Capacitor  [C0402]  (value not drawn)
C19  Capacitor  [C0402]  (value not drawn)
C24  Capacitor  [C0402]  (value not drawn)
C28  value 2.2uF  [C0603]  (hidden comment: Capacitor)
C29  value 10uF  [C0603]  (hidden comment: Capacitor)
C34  Capacitor  [C0402]  (value not drawn)
C37  value 4.7uF  [C0402]  (hidden comment: Capacitor)
C45  value 100nF  [C0402]
CN18  value P2ML4452-1-A.DXF  [ANT_MURATA_TYPE-1-DX_P2ML4452-1-A_DXF]  (hidden comment: antenna_Wifi_BLE_Murata)  (no BOM)
L1  value LQW15AN2N4C00x  [IND_0402_MURATA_LQW15AN2N4C00X]  (hidden comment: Inductor)
L4  value LQM18PN2R2MGH  [L0603]  (hidden comment: Inductor)
R8  value 0R  [R0402]  (hidden comment: Resistor)
R10  value 0R  [R0402]  (hidden comment: Resistor)
R17  value 47K  [R0402]  (hidden comment: Resistor)
R20  value 47K  [R0402]  (hidden comment: Resistor)
R22  value 47K  [R0402]  (hidden comment: Resistor)
R26  value 47K  [R0402]  (hidden comment: Resistor)
R27  value 47K  [R0402]  (hidden comment: Resistor)
TP6  Test Point  [TP_SMD_1MM]  (value not drawn)  (no BOM)
TP7  Test Point  [TP_SMD_1MM]  (value not drawn)  (no BOM)
TP11  Test Point  [TP_SMD_1MM]  (value not drawn)  (no BOM)
TP12  Test Point  [TP_SMD_1MM]  (value not drawn)  (no BOM)
TP24  Test Point  [TP_SMD_0-6MM]  (value not drawn)  (no BOM)
TP25  Test Point  [TP_SMD_0-6MM]  (value not drawn)  (no BOM)
TP26  Test Point  [TP_SMD_0-6MM]  (value not drawn)  (no BOM)
TP27  Test Point  [TP_SMD_0-6MM]  (value not drawn)  (no BOM)
TP28  Test Point  [TP_SMD_0-6MM]  (value not drawn)  (no BOM)
TP29  Test Point  [TP_SMD_0-6MM]  (value not drawn)  (no BOM)
U8  LBEE5KL1DX-883  [MOD_WLAN-BT_MURATA_LBEE5KL1DX-883]

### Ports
BT_DEV_WAKE (in), BT_HOST_WAKE (out), BT_PCM (harness BT_PCM), BT_REG_ON (in), BT_UART (harness BT_UART), LPO_32 (in), WL_HOST_WAKE (out), WL_REG_ON (in), WL_SDIO (harness WLAN_SDIO)

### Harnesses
BT_PCM: BT_PCM_CLK, BT_PCM_SDI, BT_PCM_SDO, BT_PCM_WS
BT_UART: USART2_TX, USART2_RX, USART2_CTS, USART2_RTS
WLAN_SDIO: SDMMC2_D[0..3], SDMMC2_CMD, SDMMC2_CK

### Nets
3V3: C28.2 C29.2 C45.2 R17.1 R20.1 R22.1 R26.1 R27.1 U8.30(VBAT) U8.36(VIO)
GND: C8.1 C19.1 C24.1 C28.1 C29.1 C34.1 C37.1 C45.1 U8.1(GND) U8.12(GND) U8.19(GND) U8.21(GND) U8.29(GND) U8.32(GND) U8.33(GND) U8.35(GND) U8.40(GND) U8.42(GND) U8.43(GND) U8.44(GND) U8.45(GND) U8.46(GND)
BT_DEV_WAKE: U8.39(BT_DEV_WAKE) ; port BT_DEV_WAKE
BT_HOST_WAKE: U8.38(BT_HOST_WAKE) ; port BT_HOST_WAKE
BT_PCM_CLK: U8.11(BT_PCM_CLK) ; port BT_PCM.BT_PCM_CLK
BT_PCM_SDI: U8.10(BT_PCM_OUT) ; port BT_PCM.BT_PCM_SDI
BT_PCM_SDO: U8.9(BT_PCM_IN) ; port BT_PCM.BT_PCM_SDO
BT_PCM_WS: U8.8(BT_PCM_SYNC) ; port BT_PCM.BT_PCM_WS
BT_REG_ON: TP29.1 U8.14(BT_REG_ON) ; port BT_REG_ON
LPO_32: TP26.1 U8.37(LPO_IN_(32kHz)) ; port LPO_32
SDMMC2_CK: TP25.1 U8.20(SDIO_CLK) ; port WL_SDIO.SDMMC2_CK
SDMMC2_CMD: R26.2 U8.22(SDIO_CMD) ; port WL_SDIO.SDMMC2_CMD
SDMMC2_D0: R22.2 U8.24(SDIO_DATA_0)
SDMMC2_D1: R17.2 U8.26(SDIO_DATA_1)
SDMMC2_D2: R27.2 U8.23(SDIO_DATA_2)
SDMMC2_D3: R20.2 U8.25(SDIO_DATA_3)
USART2_CTS: U8.5(BT_UART_RTS_N) ; port BT_UART.USART2_CTS
USART2_RTS: U8.4(BT_UART_CTS_N) ; port BT_UART.USART2_RTS
USART2_RX: TP27.1 U8.3(BT_UART_TXD) ; port BT_UART.USART2_RX
USART2_TX: TP28.1 U8.2(BT_UART_RXD) ; port BT_UART.USART2_TX
WL_HOST_WAKE: U8.27(WL_GPIO_0_HOST__WAKE) ; port WL_HOST_WAKE
WL_REG_ON: TP24.1 U8.28(WL_REG_ON) ; port WL_REG_ON
NetC8_2: C8.2 L1.1 R8.1
NetC19_2: C19.2 C24.2 R8.2 R10.1
NetC34_2: C34.2 R10.2 U8.41(ANT)
NetC37_2: C37.2 L4.2 U8.31(VIN_LDO)
NetL4_1: L4.1 U8.34(SR_VLX)
NetTP6_1: TP6.1 U8.17(WL_GPIO_2)
NetTP7_1: TP7.1 U8.18(WL_GPIO_1)
NetTP11_1: TP11.1 U8.6(BT_GPIO_3)
NetTP12_1: TP12.1 U8.7(BT_GPIO_4)

Not connected (* = marked no-connect by the designer): L1 2*; U8 13(BT_GPIO_5)* 15(WL_GPIO_4)* 16(BT_I2S_dO)*

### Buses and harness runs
bus SDMMC2_D[0..3]

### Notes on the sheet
- BT_PCM = I2S1

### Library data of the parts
C8 C19 C24 C34 = MCD-00200: Capacitor, MLCC, 12pF, 50V, NPO, 5%, 0402, T=0,5mm; Manufacturer_Part_Number: CC0402JRNPO9BN120; Manufacturer: YAGEO; Provided_By: SUBCO
C28 = MCD-00012: Capacitor, MLCC, 2.2uF, 10V, X5R, 10%, 0603, T=0,8mm; Manufacturer_Part_Number: CC0603KRX5R6BB225; Manufacturer: YAGEO; Alternate_Manufacturer_Part_Number: C0603C225K8PACTU; Alternate_Manufacturer: KEMET; Provided_By: SUBCO; Initial_Board_Reference: MB1274
C29 = MCD-00099: Capacitor, MLCC, 10uF, 10V, X5R, 10%, 0603, T=0,8mm; Manufacturer_Part_Number: GRM188R61A106KE69D; Manufacturer: MURATA; ECCN_US: EAR99; ECCN_EU: NEC; Provided_By: SUBCO; Initial_Board_Reference: MB1262
C37 = MCD-01356: as C49 on sheet Peripherals
C45 = MCD-00006: Capacitor,100nF,16V,X7R,10%,0402; Manufacturer_Part_Number: CC0402KRX7R7BB104; Manufacturer: YAGEO; Alternate_Manufacturer: MURATA; Alternate_Manufacturer_Part_Number: GCM155R71C104KA55D; Provided_By: SUBCO; Initial_Board_Reference: MB1274
CN18 = MCD-00656: Murata_Type1DX_AntennaDesign_P2ML4452-1-A.DXF; Part_Type: Misc; Manufacturer: MURATA; Initial_Board_Reference: MB1272
L1 = MCD-00657: Inductor,2.4nH,+-0.2nH,0.05R,0.85A,0402; Manufacturer: MURATA; Provided_By: SUBCO; Initial_Board_Reference: MB1272
L4 = MCD-00659: Inductor, 2.2µH, 20%, Isat 0.35A, DCR 0.2Ohm, 0603; Manufacturer: MURATA; Provided_By: SUBCO; Initial_Board_Reference: MB1272
R8 R10 = MCD-00052: Resistor,0R,0402,5%,1/16W; Manufacturer_Part_Number: RC0402JR-070RL; Manufacturer: YAGEO; Provided_By: SUBCO; Initial_Board_Reference: MB1274
R17 R20 R22 R26 R27 = MCD-00063: Resistor,47K,0402,1%,1/16W; Manufacturer_Part_Number: RC0402FR-0747KL; Manufacturer: YAGEO; Provided_By: SUBCO; Initial_Board_Reference: MB1274
TP6 TP7 TP11 TP12 = MCD-00074: as TP20 on sheet ST_LINK_V2-1
TP24-TP29 = MCD-00631: Test Point 0.6mm; Part_Type: Mechanical; Initial_Board_Reference: MB1264
U8 = MCD-00268: IEEE802.11b/g/n W-LAN + Bluetooth 4.1+EDR module; Manufacturer: MURATA; Part_Type: IC; Provided_By: SUBCO; ECCN_US: 5A992C; Initial_Board_Reference: MB1272

## Sheet Ethernet.SchDoc: Ethernet
size A4; Date: 01-DEC-2013; CompanyName: STMicroelectronics; Organization: Microcontrollers Division; Address1: 12, Rue Jules HOROWITZ; Address2: 38019 Grenoble; Address3: FRANCE; DocumentNumber: MB1272; Revision: A-01; SheetNumber: 12; SheetTotal: 15; Project: STM32MP15-DISCO PI

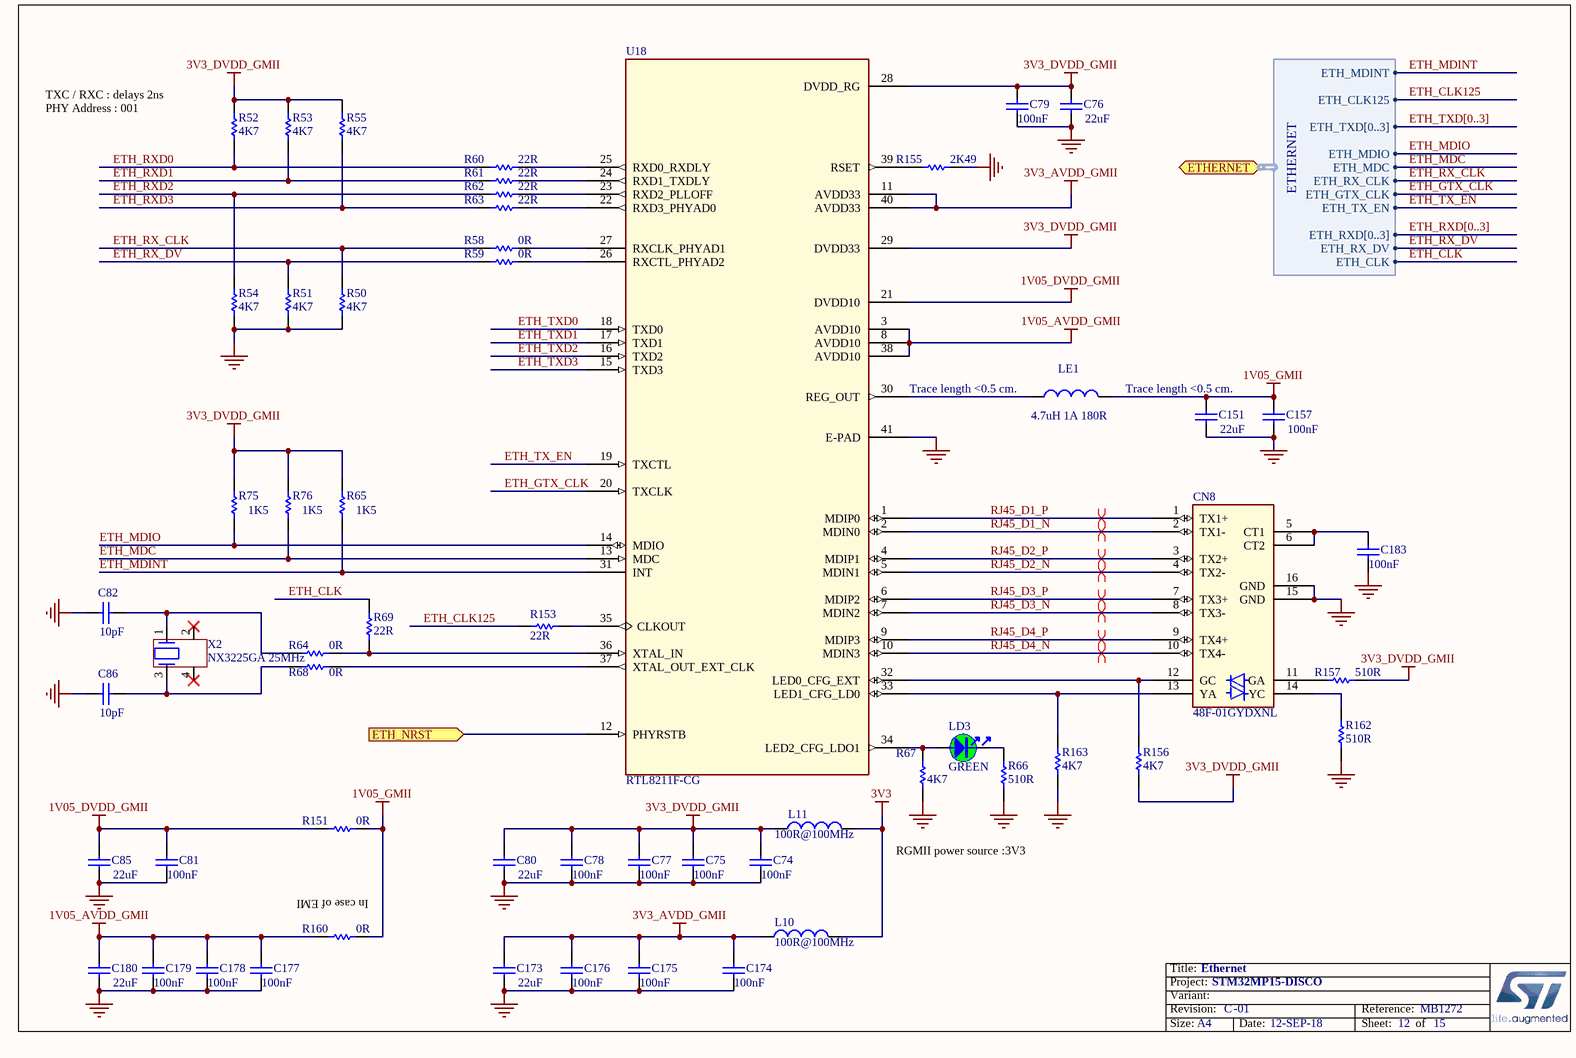
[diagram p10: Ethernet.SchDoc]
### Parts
C74  value 100nF  [C0402]
C75  value 100nF  [C0402]
C76  value 22uF  [C0603]
C77  value 100nF  [C0402]
C78  value 100nF  [C0402]
C79  value 100nF  [C0402]
C80  value 22uF  [C0603]
C81  value 100nF  [C0402]
C82  value 10pF  [C0402]
C85  value 22uF  [C0603]
C86  value 10pF  [C0402]
C151  value 22uF  [C0603]
C157  value 100nF  [C0402]
C173  value 22uF  [C0603]
C174  value 100nF  [C0402]
C175  value 100nF  [C0402]
C176  value 100nF  [C0402]
C177  value 100nF  [C0402]
C178  value 100nF  [C0402]
C179  value 100nF  [C0402]
C180  value 22uF  [C0603]
C183  value 100nF  [C0402]
CN8  value 48F-01GYDXNL  [CON_RJ45_YD_48F-01GYDXNL_LED-P]  (hidden comment: ​New part for use of led pulled down on pin 13/14 , schematic more lisible.)
L10  value 100R@100MHz  [FIL_0603_H0P65]
L11  value 100R@100MHz  [FIL_0603_H0P65]
LD3  value GREEN  [LED_0603_GREEN]
LE1  value 4.7uH 1A 180R  [L1210_LQH]
R50  value 4K7  [R0402]
R51  value 4K7  [R0402]
R52  value 4K7  [R0402]
R53  value 4K7  [R0402]
R54  value 4K7  [R0402]
R55  value 4K7  [R0402]
R58  value 0R  [R0402]
R59  value 0R  [R0402]
R60  value 22R  [R0402]
R61  value 22R  [R0402]
R62  value 22R  [R0402]
R63  value 22R  [R0402]
R64  value 0R  [R0402]
R65  value 1K5  [R0402]
R66  value 510R  [R0402]
R67  value 4K7  [R0402]
R68  value 0R  [R0402]
R69  value 22R  [R0402]
R75  value 1K5  [R0402]
R76  value 1K5  [R0402]
R151  value 0R  [R0603]
R153  value 22R  [R0402]
R155  value 2K49  [R0402]
R156  value 4K7  [R0402]
R157  value 510R  [R0402]
R160  value 0R  [R0603]
R162  value 510R  [R0402]
R163  value 4K7  [R0402]
U18  RTL8211F-CG  [ICC_QFN40-EPAD_5X5_P040]
X2  value NX3225GA 25MHz  [CRY_NX3225HA_4P]  (hidden comment: XTAL_4_PINS)

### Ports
ETH_NRST (in), ETHERNET (harness ETHERNET)

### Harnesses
ETHERNET: ETH_MDINT, ETH_CLK125, ETH_TXD[0..3], ETH_MDIO, ETH_MDC, ETH_RX_CLK, ETH_GTX_CLK, ETH_TX_EN, ETH_RXD[0..3], ETH_RX_DV, ETH_CLK

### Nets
1V05_AVDD_GMII: C177.2 C178.2 C179.2 C180.2 R160.1 U18.3(AVDD10) U18.8(AVDD10) U18.38(AVDD10)
1V05_DVDD_GMII: C81.2 C85.2 R151.1 U18.21(DVDD10)
1V05_GMII: C151.2 C157.2 LE1.2 R151.2 R160.2
3V3: L10.2 L11.2
3V3_AVDD_GMII: C173.2 C174.2 C175.2 C176.2 L10.1 U18.11(AVDD33) U18.40(AVDD33)
3V3_DVDD_GMII: C74.2 C75.2 C76.1 C77.2 C78.2 C79.2 C80.2 L11.1 R52.2 R53.2 R55.2 R65.2 R75.2 R76.2 R156.1 R157.2 U18.28(DVDD_RG) U18.29(DVDD33)
GND: C74.1 C75.1 C76.2 C77.1 C78.1 C79.1 C80.1 C81.1 C82.1 C85.1 C86.1 C151.1 C157.1 C173.1 C174.1 C175.1 C176.1 C177.1 C178.1 C179.1 C180.1 C183.1 CN8.15(GND) CN8.16(GND) R50.1 R51.1 R54.1 R66.1 R67.1 R155.2 R162.1 R163.1 U18.41(E-PAD)
ETH_CLK: R69.2 ; port ETHERNET.ETH_CLK
ETH_CLK125: R153.1 ; port ETHERNET.ETH_CLK125
ETH_GTX_CLK: U18.20(TXCLK) ; port ETHERNET.ETH_GTX_CLK
ETH_MDC: R76.1 U18.13(MDC) ; port ETHERNET.ETH_MDC
ETH_MDINT: R65.1 U18.31(INT) ; port ETHERNET.ETH_MDINT
ETH_MDIO: R75.1 U18.14(MDIO) ; port ETHERNET.ETH_MDIO
ETH_NRST: U18.12(PHYRSTB) ; port ETH_NRST
ETH_RX_CLK: R50.2 R58.1 ; port ETHERNET.ETH_RX_CLK
ETH_RX_DV: R51.2 R59.1 ; port ETHERNET.ETH_RX_DV
ETH_RXD0: R52.1 R60.1
ETH_RXD1: R53.1 R61.1
ETH_RXD2: R54.2 R62.1
ETH_RXD3: R55.1 R63.1
ETH_TX_EN: U18.19(TXCTL) ; port ETHERNET.ETH_TX_EN
ETH_TXD0: U18.18(TXD0)
ETH_TXD1: U18.17(TXD1)
ETH_TXD2: U18.16(TXD2)
ETH_TXD3: U18.15(TXD3)
RJ45_D1_N: CN8.2(TX1-) U18.2(MDIN0)
RJ45_D1_P: CN8.1(TX1+) U18.1(MDIP0)
RJ45_D2_N: CN8.4(TX2-) U18.5(MDIN1)
RJ45_D2_P: CN8.3(TX2+) U18.4(MDIP1)
RJ45_D3_N: CN8.8(TX3-) U18.7(MDIN2)
RJ45_D3_P: CN8.7(TX3+) U18.6(MDIP2)
RJ45_D4_N: CN8.10(TX4-) U18.10(MDIN3)
RJ45_D4_P: CN8.9(TX4+) U18.9(MDIP3)
NetC82_2: C82.2 R64.1 X2.1
NetC86_2: C86.2 R68.1 X2.3
NetC183_2: C183.2 CN8.5(CT1) CN8.6(CT2)
NetCN8_11: CN8.11(GA) R157.1
NetCN8_12: CN8.12(GC) R156.2 U18.32(LED0_CFG_EXT)
NetCN8_13: CN8.13(YA) R163.2 U18.33(LED1_CFG_LD0)
NetCN8_14: CN8.14(YC) R162.2
NetLD3_1: LD3.1 R67.2 U18.34(LED2_CFG_LDO1)
NetLD3_2: LD3.2 R66.2
NetLE1_1: LE1.1 U18.30(REG_OUT)
NetR58_2: R58.2 U18.27(RXCLK_PHYAD1)
NetR59_2: R59.2 U18.26(RXCTL_PHYAD2)
NetR60_2: R60.2 U18.25(RXD0_RXDLY)
NetR61_2: R61.2 U18.24(RXD1_TXDLY)
NetR62_2: R62.2 U18.23(RXD2_PLLOFF)
NetR63_2: R63.2 U18.22(RXD3_PHYAD0)
NetR64_2: R64.2 R69.1 U18.36(XTAL_IN)
NetR68_2: R68.2 U18.37(XTAL_OUT_EXT_CLK)
NetR153_2: R153.2 U18.35(CLKOUT)
NetR155_1: R155.1 U18.39(RSET)

Not connected (* = marked no-connect by the designer): X2 2* 4*

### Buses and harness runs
bus ETH_RXD[0..3]
bus ETH_TXD[0..3]

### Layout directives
differential pair: RJ45_D1_N, RJ45_D1_P, RJ45_D2_N, RJ45_D2_P, RJ45_D3_N, RJ45_D3_P, RJ45_D4_N, RJ45_D4_P

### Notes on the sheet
- (near R52) TXC / RXC : delays 2ns
  PHY Address : 001
- (near LE1) Trace length <0.5 cm.
- (near C151) Trace length <0.5 cm.
- (near R160) In case of EMI
- RGMII power source :3V3

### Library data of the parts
C74 C75 C77-C79 C81 C157 C174-C179 C183 = MCD-00006: as C93 on sheet ST_LINK_V2-1
C76 C80 C85 C151 C173 C180 = MCD-00100: Capacitor,22uF,6V3,X5R,20%,0603; Manufacturer_Part_Number: GRM188R60J226MEA0J; Manufacturer: MURATA; ECCN_US: EAR99; ECCN_EU: NEC; Provided_By: SUBCO; Initial_Board_Reference: mb1262
C82 C86 = MCD-00015: as C98 on sheet ST_LINK_V2-1
CN8 = MCD-01129: Connector RJ45 with Gigabit magnetics and LED , led pull down; Manufacturer: YUAN DEAN SCIENTIFIC; Provided_By: SUBCO; Initial_Board_Reference: MB1272
L10 L11 = MCD-00094: Ferrite bead 100R 2A 0603; Manufacturer_Part_Number: BLM18EG101TN1; Manufacturer: MURATA; Part_Type: Inductor; ECCN_US: EAR99; ECCN_EU: NEC; Provided_By: SUBCO; Initial_Board_Reference: mb1262
LD3 = MCD-00050: as LD5 on sheet Peripherals
LE1 = MCD-00048: FIXED IND 4.7UH 1A 180 MOHM 30% SMD; Manufacturer_Part_Number: LQH32PN4R7NN0L; Manufacturer: MURATA; Provided_By: SUBCO; Initial_Board_Reference: mb1274
R50-R55 R67 R156 R163 = MCD-00065: as R91 on sheet ST_LINK_V2-1
R58 R59 R64 R68 = MCD-00052: as R13 on sheet Peripherals
R60-R63 R69 R153 = MCD-00189: Resistor,22R,0402,1%,1/16W; Manufacturer_Part_Number: RC0402FR-0722RL; Manufacturer: YAGEO; Provided_By: SUBCO
R65 R75 R76 = MCD-00068: as R93 on sheet ST_LINK_V2-1
R66 R157 R162 = MCD-00064: as R114 on sheet GPIO_&_Arduino_ Connectors
R151 R160 = MCD-00056: Resistor,0R,0603,5%,1/10W; Manufacturer_Part_Number: RC0603JR-070RL; Manufacturer: YAGEO; Provided_By: SUBCO; Initial_Board_Reference: mb1274
R155 = MCD-00183: Resistor,2K49,0402,1%,1/16W; Manufacturer_Part_Number: RC0402FR-072K49L; Manufacturer: YAGEO; Provided_By: SUBCO
U18 = MCD-01130: 10/100/1000M GIGABIT Ethernet Transceiver, QFN40 , SMPS version; Manufacturer: REALTEK; Part_Type: IC; Provided_By: SUBCO; Initial_Board_Reference: MB1272
X2 = MCD-01463: Crystal 25Mhz, 10pF, -+50PPM, SMD; Part_Type: Crystal_Osc; Manufacturer_Part_Number: NX3225GA 25MHz EXS00A-CG06750; Manufacturer: NDK; Provided_By: SUBCO; Initial_Board_Reference: MB1272B; Remark: footprint same as CRY_NX3225HA_4P

## Sheet HDMI.SchDoc: HDMI
size A4; Date: 01-DEC-2013; CompanyName: STMicroelectronics; Organization: Microcontrollers Division; Address1: 12, Rue Jules HOROWITZ; Address2: 38019 Grenoble; Address3: FRANCE; DocumentNumber: MB1272; Revision: A-01; SheetNumber: 9; SheetTotal: 15; Project: STM32MP15-DISCO PI

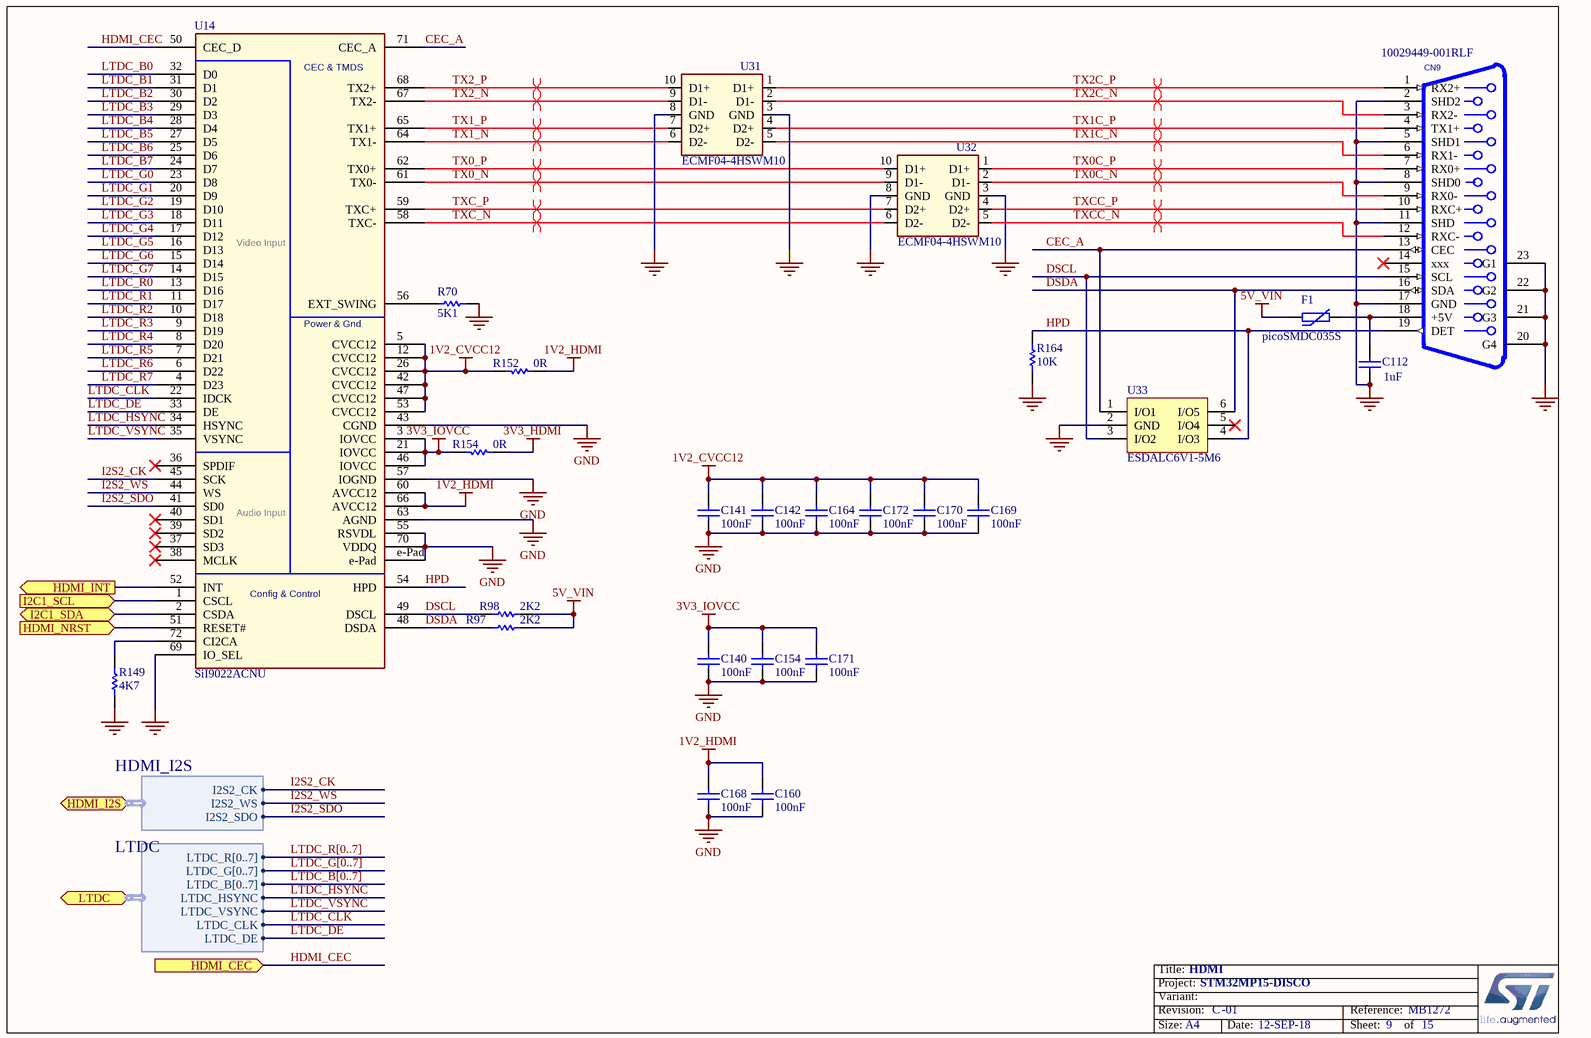
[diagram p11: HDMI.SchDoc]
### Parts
C112  value 1uF  [C0402]
C140  value 100nF  [C0402]
C141  value 100nF  [C0402]
C142  value 100nF  [C0402]
C154  value 100nF  [C0402]
C160  value 100nF  [C0402]
C164  value 100nF  [C0402]
C168  value 100nF  [C0402]
C169  value 100nF  [C0402]
C170  value 100nF  [C0402]
C171  value 100nF  [C0402]
C172  value 100nF  [C0402]
CN9  value 10029449-001RLF  [CON_HDMI_FCI-AMPHENOL_10029449-001RLF]
F1  value picoSMDC035S  [R0805]  (hidden comment: ​f)
R70  value 5K1  [R0402]
R97  value 2K2  [R0402]
R98  value 2K2  [R0402]
R149  value 4K7  [R0402]
R152  value 0R  [R0402]
R154  value 0R  [R0402]
R164  value 10K  [R0402]  (hidden comment: Resistor)
U14  value SiI9022ACNU  [ICC_QFN72-EPAD_10X10_P050]
U31  value ECMF04-4HSWM10  [ESD_UQFN-10L_2P60X1P35_P050]
U32  value ECMF04-4HSWM10  [ESD_UQFN-10L_2P60X1P35_P050]
U33  ESDALC6V1-5M6  [ESD_UQFN-6L_1P45X1_P050]

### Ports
HDMI_CEC (in), HDMI_I2S (harness HDMI_I2S), HDMI_INT (out), HDMI_NRST (in), I2C1_SCL (in), I2C1_SDA (bidir), LTDC (harness LTDC)

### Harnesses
LTDC: LTDC_R[0..7], LTDC_G[0..7], LTDC_B[0..7], LTDC_HSYNC, LTDC_VSYNC, LTDC_CLK, LTDC_DE
HDMI_I2S: I2S2_CK, I2S2_SDO, I2S2_WS

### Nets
1V2_CVCC12: C141.2 C142.2 C164.2 C169.2 C170.2 C172.2 R152.1 U14.5(CVCC12) U14.12(CVCC12) U14.26(CVCC12) U14.42(CVCC12) U14.47(CVCC12) U14.53(CVCC12)
1V2_HDMI: C160.2 C168.2 R152.2 U14.60(AVCC12) U14.66(AVCC12)
3V3_HDMI: R154.2
3V3_IOVCC: C140.2 C154.2 C171.2 R154.1 U14.3(IOVCC) U14.21(IOVCC) U14.46(IOVCC)
5V_VIN: F1.1 R97.2 R98.2
GND: C112.1 C140.1 C141.1 C142.1 C154.1 C160.1 C164.1 C168.1 C169.1 C170.1 C171.1 C172.1 CN9.2(SHD2) CN9.5(SHD1) CN9.8(SHD0) CN9.11(SHD) CN9.17(GND) CN9.20(G4) CN9.21(G3) CN9.22(G2) CN9.23(G1) R70.2 R149.1 R164.1 U14.43(CGND) U14.55(RSVDL) U14.57(IOGND) U14.63(AGND) U14.69(IO_SEL) U14.70(VDDQ) U14.e-Pad U31.3(GND) U31.8(GND) U32.3(GND) U32.8(GND) U33.2(GND)
CEC_A: CN9.13(CEC) U14.71(CEC_A) U33.1(I/O1)
DSCL: CN9.15(SCL) R98.1 U14.49(DSCL) U33.3(I/O2)
DSDA: CN9.16(SDA) R97.1 U14.48(DSDA) U33.6(I/O5)
HDMI_CEC: U14.50(CEC_D) ; port HDMI_CEC
HDMI_INT: U14.52(INT) ; port HDMI_INT
HDMI_NRST: U14.51(RESET#) ; port HDMI_NRST
HPD: CN9.19(DET) R164.2 U14.54(HPD) U33.4(I/O3)
I2C1_SCL: U14.1(CSCL) ; port I2C1_SCL
I2C1_SDA: U14.2(CSDA) ; port I2C1_SDA
I2S2_CK: U14.45(SCK) ; port HDMI_I2S.I2S2_CK
I2S2_SDO: U14.41(SD0) ; port HDMI_I2S.I2S2_SDO
I2S2_WS: U14.44(WS) ; port HDMI_I2S.I2S2_WS
LTDC_B0: U14.32(D0)
LTDC_B1: U14.31(D1)
LTDC_B2: U14.30(D2)
LTDC_B3: U14.29(D3)
LTDC_B4: U14.28(D4)
LTDC_B5: U14.27(D5)
LTDC_B6: U14.25(D6)
LTDC_B7: U14.24(D7)
LTDC_CLK: U14.22(IDCK) ; port LTDC.LTDC_CLK
LTDC_DE: U14.33(DE) ; port LTDC.LTDC_DE
LTDC_G0: U14.23(D8)
LTDC_G1: U14.20(D9)
LTDC_G2: U14.19(D10)
LTDC_G3: U14.18(D11)
LTDC_G4: U14.17(D12)
LTDC_G5: U14.16(D13)
LTDC_G6: U14.15(D14)
LTDC_G7: U14.14(D15)
LTDC_HSYNC: U14.34(HSYNC) ; port LTDC.LTDC_HSYNC
LTDC_R0: U14.13(D16)
LTDC_R1: U14.11(D17)
LTDC_R2: U14.10(D18)
LTDC_R3: U14.9(D19)
LTDC_R4: U14.8(D20)
LTDC_R5: U14.7(D21)
LTDC_R6: U14.6(D22)
LTDC_R7: U14.4(D23)
LTDC_VSYNC: U14.35(VSYNC) ; port LTDC.LTDC_VSYNC
TX0_N: U14.61(TX0-) U32.9(D1-)
TX0_P: U14.62(TX0+) U32.10(D1+)
TX0C_N: CN9.9(RX0-) U32.2(D1-)
TX0C_P: CN9.7(RX0+) U32.1(D1+)
TX1_N: U14.64(TX1-) U31.6(D2-)
TX1_P: U14.65(TX1+) U31.7(D2+)
TX1C_N: CN9.6(RX1-) U31.5(D2-)
TX1C_P: CN9.4(TX1+) U31.4(D2+)
TX2_N: U14.67(TX2-) U31.9(D1-)
TX2_P: U14.68(TX2+) U31.10(D1+)
TX2C_N: CN9.3(RX2-) U31.2(D1-)
TX2C_P: CN9.1(RX2+) U31.1(D1+)
TXC_N: U14.58(TXC-) U32.6(D2-)
TXC_P: U14.59(TXC+) U32.7(D2+)
TXCC_N: CN9.12(RXC-) U32.5(D2-)
TXCC_P: CN9.10(RXC+) U32.4(D2+)
NetC112_2: C112.2 CN9.18(+5V) F1.2
NetR70_1: R70.1 U14.56(EXT_SWING)
NetR149_2: R149.2 U14.72(CI2CA)

Not connected (* = marked no-connect by the designer): CN9 14(xxx)*; U14 36(SPDIF)* 37(SD3)* 38(MCLK)* 39(SD2)* 40(SD1)*; U33 5(I/O4)*

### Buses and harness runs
bus LTDC_B[0..7]
bus LTDC_G[0..7]
bus LTDC_R[0..7]

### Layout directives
differential pair: TX0_N, TX0_P, TX0C_N, TX0C_P, TX1_N, TX1_P, TX1C_N, TX1C_P, TX2_N, TX2_P, TX2C_N, TX2C_P, TXC_N, TXC_P, TXCC_N, TXCC_P

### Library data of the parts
C112 = MCD-00095: Capacitor,1uF,6V3,X5R,10%,0402; Manufacturer_Part_Number: GRM155R61E105KA12; Manufacturer: MURATA; Alternate_Manufacturer_Part_Number: GRM155R60J105KE19; ECCN_US: EAR99; ECCN_EU: NEC; Provided_By: SUBCO; Initial_Board_Reference: mb1262
C140-C142 C154 C160 C164 C168-C172 = MCD-00006: as C93 on sheet ST_LINK_V2-1
CN9 = MCD-00307: HDMI Receptacle Type A 19pins standard Connector; Manufacturer: FCI; Provided_By: SUBCO; Initial_Board_Reference: MB1272
F1 = MCD-01133: Surface mount resettable polyswitch fuse.I hold=0.35A and I trigger=0.75A; Part_Type: Misc; Manufacturer: TE CONNECTIVITY; Provided_By: SUBCO; Initial_Board_Reference: MB1272
R70 = MCD-00333: Resistor,5K1,0402,1%,1/16W; Manufacturer_Part_Number: RC0402FR-075K1L; Manufacturer: YAGEO; Provided_By: SUBCO; Initial_Board_Reference: mb1272
R97 R98 = MCD-00057: Resistor,2K2,0402,1%,1/16W; Manufacturer_Part_Number: RC0402FR-072K2L; Manufacturer: YAGEO; Provided_By: SUBCO; Initial_Board_Reference: mb1274
R149 = MCD-00065: as R91 on sheet ST_LINK_V2-1
R152 R154 = MCD-00052: as R13 on sheet Peripherals
R164 = MCD-00053: Resistor,10K,0402,1%,1/16W; Manufacturer_Part_Number: RC0402FR-0710KL; Manufacturer: YAGEO; Provided_By: SUBCO; Initial_Board_Reference: MB1274
U14 = MCD-00267: HDMI Transmitter, 72-pin 10 × 10 mm QFN; Part_Type: IC; Manufacturer: LATTICE; Provided_By: SUBCO; Initial_Board_Reference: MB1272
U31 U32 = MCD-00297: ESD protection & Common Filter High Speed serial Interfaces; Part_Type: Diode; Manufacturer: STMICROELECTRONICS; BMS_Part_Number: 9151127; Provided_By: SUBCO with ST control; Initial_Board_Reference: MB1272
U33 = MCD-01457: ESD protection , 5 lines; Part_Type: Diode; Manufacturer: STMICROELECTRONICS; Provided_By: SUBCO; Initial_Board_Reference: MB1272B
